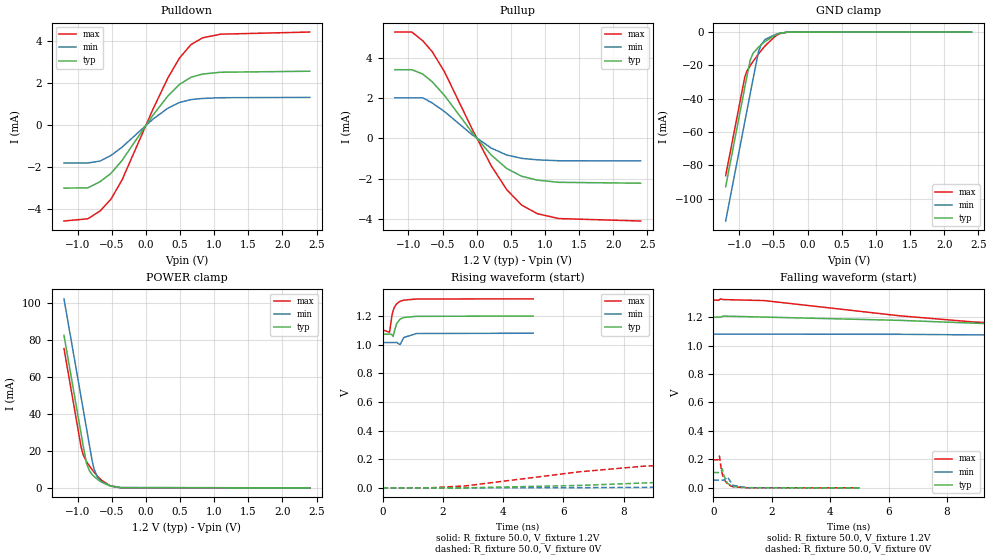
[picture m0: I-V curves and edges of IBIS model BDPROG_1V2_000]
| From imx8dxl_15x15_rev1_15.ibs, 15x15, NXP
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[Model] BDPROG_1V2_000
Model_type I/O
Polarity   Non-Inverting
Enable   Active-Low
| CAP_THRESHOLD on pad IO is "CMOS" :
| Rising=10.0% of vdde1v2   Falling=90.0% of vdde1v2
| C_comp min and max val. don't necessarily correlate with the min and max pvt
| but are the smallest and greatest pad capacitance found.
| var   typ   min   max
C_comp   2.03145pF  2.00990pF  2.05295pF
Vinl = 324.0mV
Vinh = 924.0mV
Vmeas = 600.0mV   | Reference voltage for timing measurements
Cref  = 15.0pF   | Timing specification test load capacitance value
Rref  = 1.0MOhm   | Timing specification test load resistance value
Vref  = 1.2V   | Timing specification test load voltage
[Model Spec]
| TIME_THRESHOLD on pin ZI is "CORE" :
| Rising=50.0% of vdd   Falling=50.0% of vdd
Vinl 420.00000mV 378.00000mV 462.00000mV
Vinh 780.00000mV 702.00000mV 858.00000mV
| variable   typ   min   max
[Temperature Range] 25.0 125.0 -40.0
| variable   typ   min   max
[Voltage Range] 1.2V 1.08V 1.32V
| variable   typ   min   max
[POWER Clamp Reference] 1.2V 1.08V 1.32V
| variable   typ   min   max
[GND Clamp Reference] 0V 0V 0V
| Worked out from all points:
|   slope of the pulldown table from 0 to 0.18 V, typ, clamps not added: 221 ohm
|   slope of the pullup table from 0 to 0.18 V, typ, clamps not added: 253 ohm
|   GND clamp passes 1 mA (typ) near -0.42 V on its own axis
|   POWER clamp passes 1 mA (typ) near -0.53 V on its own axis
|   rising waveform, R_fixture 50.0, V_fixture 1.2V: 20-80 % time 162ps typ, 162ps min, 164ps max; typ from 1.07 V to 1.2 V
|   falling waveform, R_fixture 50.0, V_fixture 1.2V: 20-80 % time 12ns typ, 22.9ns min, 6.95ns max; typ from 1.2 V to 1.07 V
|   rising waveform, R_fixture 50.0, V_fixture 0V: 20-80 % time 9.6ns typ, 18.1ns min, 5.33ns max; typ from 0 V to 0.108 V
|   falling waveform, R_fixture 50.0, V_fixture 0V: 20-80 % time 175ps typ, 172ps min, 171ps max; typ from 0.108 V to 0 V
[POWER Clamp]
-1.2V     82.47mA    102.2mA    75.29mA
-950mV    29.35mA    49.08mA    22.16mA
-920mV    22.97mA    42.71mA    17.94mA
-870mV    13.26mA    32.08mA    14.19mA
-830mV    9.388mA    23.58mA    11.94mA
-790mV    7.28mA     15.08mA    9.891mA
-760mV    6.153mA    10.18mA    8.467mA
-710mV    4.618mA    5.741mA    6.312mA
-650mV    3.105mA    3.261mA    4.124mA
-520mV    918uA      1.114mA    1.041mA
-370mV    66.09uA    190.5uA    36.14uA
2.4V      0A         0A         0A
[GND Clamp]
-1.2V     -92.79mA   -113.4mA   -86.23mA
-920mV    -33.29mA   -53.93mA   -27.01mA
-890mV    -26.92mA   -47.56mA   -23.57mA
-840mV    -16.83mA   -36.93mA   -20.11mA
-800mV    -12.88mA   -28.43mA   -17.73mA
-720mV    -9.099mA   -11.98mA   -13.24mA
-680mV    -7.622mA   -7.471mA   -11.12mA
-620mV    -5.599mA   -4.428mA   -8.161mA
-470mV    -1.717mA   -1.41mA    -2.413mA
-410mV    -792.7uA   -748.8uA   -1.042mA
-300mV    -72.27uA   -128.2uA   -61.83uA
2.4V      12.46nA    838.5nA    861.8pA
| variable   typ   min   max
[Pullup Reference] 1.2V 1.08V 1.32V
| variable   typ   min   max
[Pulldown Reference] 0V 0V 0V
[Pullup]
-1.2V     3.414mA    2.016mA    5.286mA
-950mV    3.414mA    2.016mA    5.286mA
-790mV    3.196mA    2.016mA    4.849mA
-650mV    2.805mA    1.756mA    4.299mA
-470mV    2.125mA    1.328mA    3.292mA
-70mV     301.4uA    184.3uA    480.9uA
210mV     -819.3uA   -477.7uA   -1.349mA
440mV     -1.499mA   -827.6uA   -2.553mA
660mV     -1.885mA   -993.6uA   -3.322mA
890mV     -2.076mA   -1.067mA   -3.745mA
1.2V      -2.183mA   -1.111mA   -3.984mA
2.4V      -2.227mA   -1.119mA   -4.106mA
[Pulldown]
-1.2V     -2.999mA   -1.803mA   -4.567mA
-850mV    -2.986mA   -1.803mA   -4.461mA
-670mV    -2.691mA   -1.711mA   -4.084mA
-510mV    -2.289mA   -1.439mA   -3.516mA
-350mV    -1.683mA   -1.051mA   -2.612mA
100mV     461.5uA    278.5uA    735.6uA
320mV     1.382mA    804uA      2.238mA
490mV     1.937mA    1.08mA     3.191mA
660mV     2.281mA    1.218mA    3.838mA
830mV     2.436mA    1.272mA    4.161mA
1.1V      2.521mA    1.307mA    4.335mA
2.4V      2.569mA    1.322mA    4.436mA
[Ramp]
dV/dt_r 64.67689mV/9.5982ns 32.22194mV/18.06622ns 118.34546mV/5.32652ns
dV/dt_f 75.44366mV/12.0013ns 37.52591mV/21.44012ns 130.11031mV/6.95246ns
R_load = 50.0
| Removed startup time: 0s 0s 0s  .
| Removed end time: 5.0ns.
[Rising Waveform]
R_fixture   = 50.0
V_fixture   = 1.2V
V_fixture_min = 1.08V
V_fixture_max = 1.32V
0s        1.074V     1.015V     1.103V
234ps     1.074V     1.015V     1.087V
308ps     1.071V     1.015V     1.198V
351ps     1.057V     1.015V     1.237V
386ps     1.088V     1.015V     1.258V
466ps     1.146V     1.016V     1.285V
581ps     1.178V     999.8mV    1.303V
707ps     1.19V      1.05V      1.311V
1.122ns   1.198V     1.078V     1.319V
5ns       1.2V       1.08V      1.32V
| Removed startup time: 0s 0s 0s  .
| Removed end time: 60.0ns.
[Falling Waveform]
R_fixture   = 50.0
V_fixture   = 1.2V
V_fixture_min = 1.08V
V_fixture_max = 1.32V
0s        1.2V       1.08V      1.32V
180ps     1.2V       1.08V      1.318V
240ps     1.199V     1.08V      1.328V
340ps     1.207V     1.08V      1.323V
1.74ns    1.2V       1.08V      1.316V
6.38ns    1.177V     1.079V     1.209V
8.94ns    1.157V     1.075V     1.165V
15.04ns   1.115V     1.064V     1.119V
28.8ns    1.081V     1.037V     1.104V
60ns      1.074V     1.015V     1.103V
| Removed startup time: 0s 0s 0s  .
| Removed end time: 60.0ns.
[Rising Waveform]
R_fixture   = 50.0
V_fixture   = 0V
V_fixture_min = 0V
V_fixture_max = 0V
0s        28.6nV     1.462uV    18.95nV
1.62ns    -93.21uV   -51.64uV   617.1uV
2.76ns    182.6uV    -35.71uV   13.7mV
6.54ns    16.71mV    1.217mV    112mV
8.64ns    33.54mV    3.383mV    150.6mV
10.78ns   51.38mV    6.514mV    172.8mV
13.52ns   70.58mV    11.56mV    186.2mV
18.36ns   91.38mV    21.93mV    194.7mV
25.48ns   102.9mV    35.55mV    196.9mV
60ns      107.8mV    53.7mV     197.2mV
| Removed startup time: 0s 0s 0s  .
| Removed end time: 4.999ns.
[Falling Waveform]
R_fixture   = 50.0
V_fixture   = 0V
V_fixture_min = 0V
V_fixture_max = 0V
0s        107.8mV    54.54mV    197.2mV
161ps     107.8mV    54.54mV    196.7mV
208ps     107.7mV    54.53mV    223.7mV
265ps     117.5mV    54.57mV    137.3mV
304ps     133.8mV    54.6mV     97.44mV
367ps     81.44mV    53.79mV    58.53mV
486ps     30.71mV    75.45mV    24.78mV
671ps     9.168mV    17.53mV    7.149mV
1.157ns   749uV      1.208mV    534.8uV
4.999ns   25.73uV    20.62uV    28.93uV
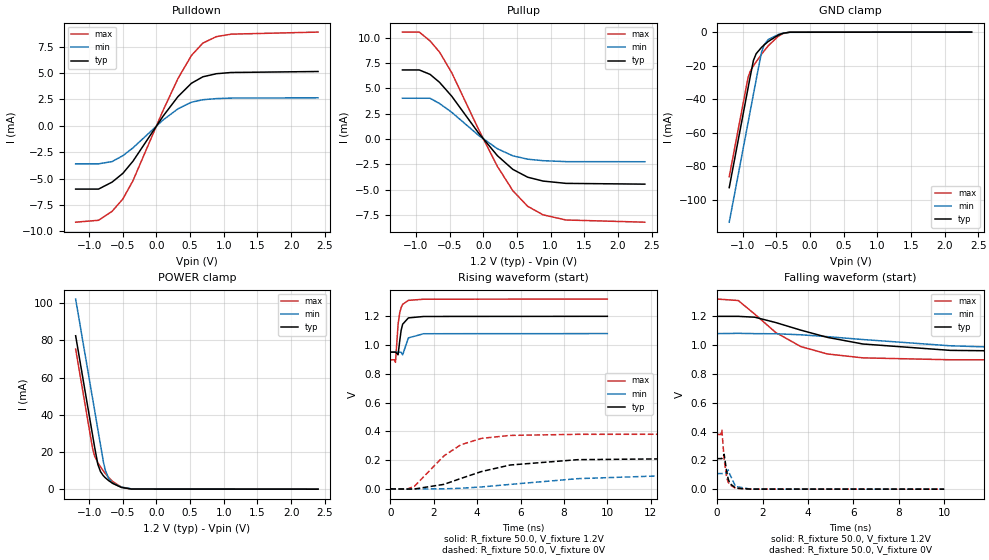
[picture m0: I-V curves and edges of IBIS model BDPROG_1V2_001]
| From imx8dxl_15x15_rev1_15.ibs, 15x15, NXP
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[Model] BDPROG_1V2_001
Model_type I/O
Polarity   Non-Inverting
Enable   Active-Low
| CAP_THRESHOLD on pad IO is "CMOS" :
| Rising=10.0% of vdde1v2   Falling=90.0% of vdde1v2
| C_comp min and max val. don't necessarily correlate with the min and max pvt
| but are the smallest and greatest pad capacitance found.
| var   typ   min   max
C_comp   2.03110pF  2.00945pF  2.05275pF
Vinl = 324.0mV
Vinh = 924.0mV
Vmeas = 600.0mV   | Reference voltage for timing measurements
Cref  = 15.0pF   | Timing specification test load capacitance value
Rref  = 1.0MOhm   | Timing specification test load resistance value
Vref  = 1.2V   | Timing specification test load voltage
[Model Spec]
| TIME_THRESHOLD on pin ZI is "CORE" :
| Rising=50.0% of vdd   Falling=50.0% of vdd
Vinl 420.00000mV 378.00000mV 462.00000mV
Vinh 780.00000mV 702.00000mV 858.00000mV
| variable   typ   min   max
[Temperature Range] 25.0 125.0 -40.0
| variable   typ   min   max
[Voltage Range] 1.2V 1.08V 1.32V
| variable   typ   min   max
[POWER Clamp Reference] 1.2V 1.08V 1.32V
| variable   typ   min   max
[GND Clamp Reference] 0V 0V 0V
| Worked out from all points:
|   slope of the pulldown table from 0 to 0.18 V, typ, clamps not added: 111 ohm
|   slope of the pullup table from 0 to 0.18 V, typ, clamps not added: 127 ohm
|   GND clamp passes 1 mA (typ) near -0.43 V on its own axis
|   POWER clamp passes 1 mA (typ) near -0.53 V on its own axis
|   rising waveform, R_fixture 50.0, V_fixture 1.2V: 20-80 % time 168ps typ, 182ps min, 165ps max; typ from 0.951 V to 1.2 V
|   falling waveform, R_fixture 50.0, V_fixture 1.2V: 20-80 % time 4ns typ, 7.65ns min, 2.31ns max; typ from 1.2 V to 0.951 V
|   rising waveform, R_fixture 50.0, V_fixture 0V: 20-80 % time 2.98ns typ, 5.7ns min, 1.67ns max; typ from 0 V to 0.212 V
|   falling waveform, R_fixture 50.0, V_fixture 0V: 20-80 % time 174ps typ, 206ps min, 165ps max; typ from 0.212 V to 0 V
[POWER Clamp]
-1.2V     82.47mA    102.2mA    75.29mA
-950mV    29.35mA    49.08mA    22.16mA
-920mV    22.97mA    42.71mA    17.94mA
-870mV    13.26mA    32.08mA    14.19mA
-830mV    9.388mA    23.58mA    11.94mA
-790mV    7.28mA     15.08mA    9.891mA
-760mV    6.153mA    10.18mA    8.467mA
-710mV    4.618mA    5.741mA    6.312mA
-650mV    3.105mA    3.261mA    4.124mA
-520mV    918uA      1.114mA    1.041mA
-370mV    66.09uA    190.5uA    36.14uA
2.4V      0A         0A         0A
[GND Clamp]
-1.2V     -92.79mA   -113.4mA   -86.23mA
-920mV    -33.29mA   -53.93mA   -27.01mA
-890mV    -26.92mA   -47.56mA   -23.57mA
-840mV    -16.83mA   -36.93mA   -20.11mA
-800mV    -12.88mA   -28.43mA   -17.73mA
-720mV    -9.099mA   -11.98mA   -13.24mA
-680mV    -7.622mA   -7.471mA   -11.12mA
-620mV    -5.599mA   -4.428mA   -8.161mA
-470mV    -1.717mA   -1.41mA    -2.413mA
-400mV    -678.8uA   -662.4uA   -876.2uA
-300mV    -72.27uA   -128.2uA   -61.83uA
2.4V      12.46nA    838.5nA    861.8pA
| variable   typ   min   max
[Pullup Reference] 1.2V 1.08V 1.32V
| variable   typ   min   max
[Pulldown Reference] 0V 0V 0V
[Pullup]
-1.2V     6.828mA    4.033mA    10.57mA
-950mV    6.828mA    4.033mA    10.57mA
-790mV    6.393mA    4.033mA    9.698mA
-650mV    5.609mA    3.514mA    8.599mA
-470mV    4.251mA    2.657mA    6.584mA
-70mV     602.8uA    368.8uA    962uA
210mV     -1.639mA   -956.2uA   -2.698mA
440mV     -2.998mA   -1.657mA   -5.106mA
660mV     -3.77mA    -1.99mA    -6.645mA
890mV     -4.153mA   -2.138mA   -7.491mA
1.23V     -4.38mA    -2.23mA    -7.998mA
2.4V      -4.456mA   -2.241mA   -8.215mA
[Pulldown]
-1.2V     -5.997mA   -3.607mA   -9.133mA
-860mV    -5.997mA   -3.607mA   -8.951mA
-660mV    -5.342mA   -3.395mA   -8.112mA
-500mV    -4.516mA   -2.838mA   -6.942mA
-350mV    -3.366mA   -2.103mA   -5.224mA
100mV     923.1uA    557.3uA    1.471mA
320mV     2.764mA    1.609mA    4.477mA
520mV     4.028mA    2.229mA    6.66mA
690mV     4.639mA    2.467mA    7.832mA
890mV     4.929mA    2.571mA    8.443mA
1.11V     5.045mA    2.621mA    8.677mA
2.4V      5.139mA    2.648mA    8.872mA
[Ramp]
dV/dt_r 127.30357mV/2.97994ns 65.04281mV/5.69568ns 228.15538mV/1.66687ns
dV/dt_f 149.19334mV/4.00144ns 77.64787mV/7.65239ns 253.69517mV/2.30909ns
R_load = 50.0
| Removed startup time: 0s 0s 0s  .
| Removed end time: 10.0ns.
[Rising Waveform]
R_fixture   = 50.0
V_fixture   = 1.2V
V_fixture_min = 1.08V
V_fixture_max = 1.32V
0s        951.3mV    950.6mV    897.2mV
194ps     951.3mV    950.6mV    897.9mV
238ps     951.3mV    950.6mV    880.1mV
358ps     932.5mV    950.6mV    1.145V
434ps     1.029V     950.7mV    1.225V
498ps     1.102V     949.8mV    1.261V
568ps     1.145V     932.4mV    1.283V
832ps     1.189V     1.05V      1.311V
1.536ns   1.199V     1.079V     1.319V
10ns      1.2V       1.08V      1.32V
| Removed startup time: 0s 0s 0s  .
| Removed end time: 50.0ns.
[Falling Waveform]
R_fixture   = 50.0
V_fixture   = 1.2V
V_fixture_min = 1.08V
V_fixture_max = 1.32V
0s        1.2V       1.08V      1.32V
930ps     1.2V       1.082V     1.31V
1.66ns    1.194V     1.08V      1.215V
2.58ns    1.157V     1.079V     1.088V
3.69ns    1.104V     1.072V     989.9mV
4.86ns    1.054V     1.059V     938.7mV
6.42ns    1.008V     1.039V     911.7mV
10.27ns   963.7mV    995.5mV    898.5mV
17.17ns   952.2mV    961.2mV    897.2mV
50ns      951.3mV    950.6mV    897.2mV
| Removed startup time: 0s 0s 0s  .
| Removed end time: 50.0ns.
[Rising Waveform]
R_fixture   = 50.0
V_fixture   = 0V
V_fixture_min = 0V
V_fixture_max = 0V
0s        23.45nV    1.263uV    14.77nV
780ps     -805.7uV   -1.627mV   -317.3uV
1.1ns     -522.4uV   -454.3uV   16.86mV
2.47ns    31.75mV    737.5uV    229.6mV
3.24ns    72.27mV    4.677mV    306.8mV
4.2ns     120.9mV    13.76mV    351.4mV
5.52ns    166.3mV    31.44mV    372.1mV
8.64ns    203.5mV    71.49mV    379.7mV
14.61ns   211.8mV    101.7mV    380.3mV
50ns      212.2mV    108.4mV    380.3mV
| Removed startup time: 0s 0s 0s  .
| Removed end time: 10.0ns.
[Falling Waveform]
R_fixture   = 50.0
V_fixture   = 0V
V_fixture_min = 0V
V_fixture_max = 0V
0s        212.2mV    108.4mV    380.3mV
162ps     212.2mV    108.4mV    379.7mV
210ps     212mV      108.4mV    409.7mV
310ps     242.1mV    108.5mV    208.1mV
418ps     124.7mV    115.8mV    83.06mV
488ps     70.9mV     133.9mV    48.91mV
560ps     39.73mV    101.9mV    29.64mV
818ps     7.306mV    18.36mV    5.66mV
1.468ns   479.1uV    644.1uV    262.1uV
10ns      7.665uV    25.72uV    1.235uV
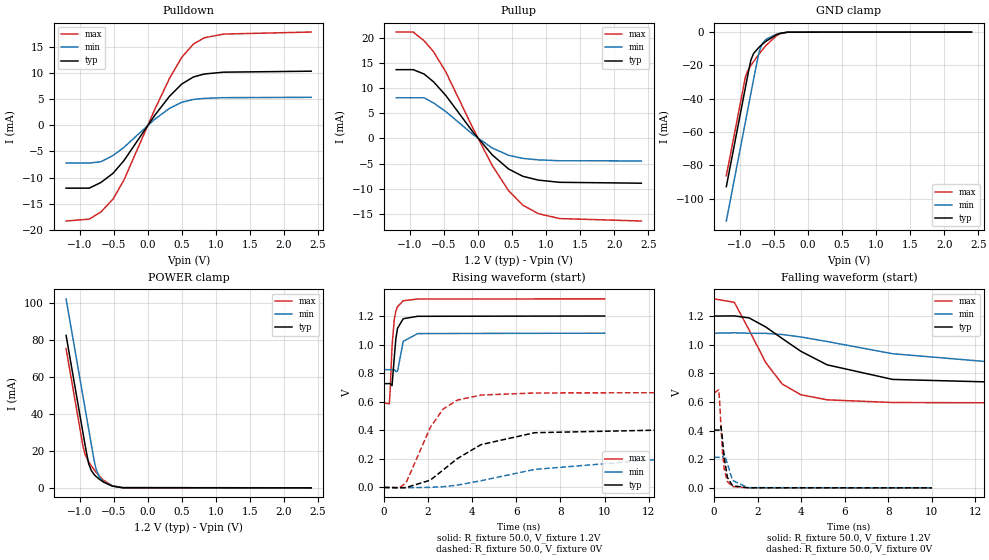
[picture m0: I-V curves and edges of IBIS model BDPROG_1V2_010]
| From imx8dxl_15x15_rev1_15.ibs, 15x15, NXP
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[Model] BDPROG_1V2_010
Model_type I/O
Polarity   Non-Inverting
Enable   Active-Low
| CAP_THRESHOLD on pad IO is "CMOS" :
| Rising=10.0% of vdde1v2   Falling=90.0% of vdde1v2
| C_comp min and max val. don't necessarily correlate with the min and max pvt
| but are the smallest and greatest pad capacitance found.
| var   typ   min   max
C_comp   2.03030pF  2.00855pF  2.05215pF
Vinl = 324.0mV
Vinh = 924.0mV
Vmeas = 600.0mV   | Reference voltage for timing measurements
Cref  = 15.0pF   | Timing specification test load capacitance value
Rref  = 1.0MOhm   | Timing specification test load resistance value
Vref  = 1.2V   | Timing specification test load voltage
[Model Spec]
| TIME_THRESHOLD on pin ZI is "CORE" :
| Rising=50.0% of vdd   Falling=50.0% of vdd
Vinl 420.00000mV 378.00000mV 462.00000mV
Vinh 780.00000mV 702.00000mV 858.00000mV
| variable   typ   min   max
[Temperature Range] 25.0 125.0 -40.0
| variable   typ   min   max
[Voltage Range] 1.2V 1.08V 1.32V
| variable   typ   min   max
[POWER Clamp Reference] 1.2V 1.08V 1.32V
| variable   typ   min   max
[GND Clamp Reference] 0V 0V 0V
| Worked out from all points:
|   slope of the pulldown table from 0 to 0.18 V, typ, clamps not added: 55.2 ohm
|   slope of the pullup table from 0 to 0.18 V, typ, clamps not added: 63.3 ohm
|   GND clamp passes 1 mA (typ) near -0.43 V on its own axis
|   POWER clamp passes 1 mA (typ) near -0.53 V on its own axis
|   rising waveform, R_fixture 50.0, V_fixture 1.2V: 20-80 % time 174ps typ, 200ps min, 167ps max; typ from 0.727 V to 1.2 V
|   falling waveform, R_fixture 50.0, V_fixture 1.2V: 20-80 % time 3.34ns typ, 6.64ns min, 1.66ns max; typ from 1.2 V to 0.727 V
|   rising waveform, R_fixture 50.0, V_fixture 0V: 20-80 % time 2.42ns typ, 4.69ns min, 1.23ns max; typ from 0 V to 0.403 V
|   falling waveform, R_fixture 50.0, V_fixture 0V: 20-80 % time 204ps typ, 267ps min, 183ps max; typ from 0.403 V to 0 V
[POWER Clamp]
-1.2V     82.47mA    102.2mA    75.29mA
-950mV    29.35mA    49.08mA    22.16mA
-920mV    22.97mA    42.71mA    17.94mA
-870mV    13.26mA    32.08mA    14.19mA
-830mV    9.388mA    23.58mA    11.94mA
-790mV    7.28mA     15.08mA    9.891mA
-760mV    6.153mA    10.18mA    8.467mA
-710mV    4.618mA    5.741mA    6.312mA
-650mV    3.105mA    3.261mA    4.124mA
-520mV    918uA      1.114mA    1.041mA
-370mV    66.09uA    190.5uA    36.14uA
2.4V      0A         0A         0A
[GND Clamp]
-1.2V     -92.79mA   -113.4mA   -86.23mA
-920mV    -33.29mA   -53.93mA   -27.01mA
-890mV    -26.92mA   -47.56mA   -23.57mA
-840mV    -16.83mA   -36.93mA   -20.11mA
-800mV    -12.88mA   -28.43mA   -17.73mA
-720mV    -9.099mA   -11.98mA   -13.24mA
-680mV    -7.622mA   -7.471mA   -11.12mA
-620mV    -5.599mA   -4.428mA   -8.161mA
-470mV    -1.717mA   -1.41mA    -2.413mA
-410mV    -792.7uA   -748.8uA   -1.042mA
-300mV    -72.27uA   -128.2uA   -61.83uA
2.4V      12.46nA    838.5nA    861.8pA
| variable   typ   min   max
[Pullup Reference] 1.2V 1.08V 1.32V
| variable   typ   min   max
[Pulldown Reference] 0V 0V 0V
[Pullup]
-1.2V     13.66mA    8.065mA    21.14mA
-950mV    13.66mA    8.065mA    21.14mA
-790mV    12.79mA    8.065mA    19.4mA
-650mV    11.22mA    7.028mA    17.2mA
-470mV    8.502mA    5.315mA    13.17mA
-70mV     1.206mA    737.6uA    1.924mA
210mV     -3.278mA   -1.913mA   -5.396mA
450mV     -6.089mA   -3.358mA   -10.39mA
660mV     -7.542mA   -3.98mA    -13.29mA
890mV     -8.306mA   -4.277mA   -14.98mA
1.2V      -8.736mA   -4.45mA    -15.94mA
2.4V      -8.914mA   -4.483mA   -16.43mA
[Pulldown]
-1.2V     -12.01mA   -7.227mA   -18.28mA
-860mV    -12.01mA   -7.227mA   -17.92mA
-690mV    -10.94mA   -6.971mA   -16.57mA
-510mV    -9.17mA    -5.771mA   -14.08mA
-350mV    -6.746mA   -4.217mA   -10.46mA
100mV     1.85mA     1.118mA    2.948mA
320mV     5.542mA    3.229mA    8.971mA
500mV     7.874mA    4.387mA    12.98mA
670mV     9.203mA    4.916mA    15.49mA
830mV     9.77mA     5.118mA    16.68mA
1.11V     10.12mA    5.261mA    17.39mA
2.4V      10.31mA    5.317mA    17.78mA
[Ramp]
dV/dt_r 242.09871mV/2.42005ns 127.7254mV/4.69138ns 397.84126mV/1.23243ns
dV/dt_f 283.93319mV/3.33551ns 153.41934mV/6.6439ns 436.07219mV/1.65617ns
R_load = 50.0
| Removed startup time: 0s 0s 0s  .
| Removed end time: 10.0ns.
[Rising Waveform]
R_fixture   = 50.0
V_fixture   = 1.2V
V_fixture_min = 1.08V
V_fixture_max = 1.32V
0s        726.8mV    824.3mV    593.2mV
242ps     726.7mV    824.3mV    584.3mV
282ps     727.5mV    824.3mV    674.7mV
366ps     712.5mV    824.3mV    985.8mV
468ps     909.3mV    825.2mV    1.177V
540ps     1.041V     812mV      1.234V
616ps     1.114V     812.8mV    1.266V
874ps     1.181V     1.023V     1.307V
1.528ns   1.198V     1.077V     1.319V
10ns      1.2V       1.08V      1.32V
| Removed startup time: 0s 0s 0s  .
| Removed end time: 50.0ns.
[Falling Waveform]
R_fixture   = 50.0
V_fixture   = 1.2V
V_fixture_min = 1.08V
V_fixture_max = 1.32V
0s        1.2V       1.08V      1.32V
930ps     1.201V     1.083V     1.296V
1.61ns    1.187V     1.08V      1.102V
2.37ns    1.124V     1.079V     875.2mV
3.13ns    1.043V     1.071V     725.2mV
3.98ns    954.3mV    1.054V     650.6mV
5.19ns    859.3mV    1.022V     614.8mV
8.2ns     757.3mV    936.8mV    596mV
15.48ns   728.3mV    844.1mV    593.1mV
50ns      726.8mV    824.3mV    593.2mV
| Removed startup time: 0s 0s 0s  .
| Removed end time: 50.0ns.
[Rising Waveform]
R_fixture   = 50.0
V_fixture   = 0V
V_fixture_min = 0V
V_fixture_max = 0V
0s        16.87nV    971.4nV    10.17nV
710ps     -2.17mV    -2.802mV   -1.024mV
1ns       -1.119mV   -1.756mV   31.17mV
2.1ns     51.02mV    583uV      420mV
2.68ns    122mV      5.245mV    548.5mV
3.33ns    202.4mV    16.13mV    611.4mV
4.4ns     299.7mV    46.95mV    646.6mV
6.83ns    383.2mV    126.3mV    661.3mV
12.91ns   402.7mV    202.2mV    663.2mV
50ns      403.5mV    212.9mV    663.1mV
| Removed startup time: 0s 0s 0s  .
| Removed end time: 10.0ns.
[Falling Waveform]
R_fixture   = 50.0
V_fixture   = 0V
V_fixture_min = 0V
V_fixture_max = 0V
0s        403.5mV    212.9mV    663.1mV
214ps     403.2mV    212.9mV    684.4mV
254ps     406.8mV    212.9mV    609.5mV
320ps     428.3mV    212.9mV    418.4mV
392ps     327.9mV    213.7mV    241.4mV
464ps     213.9mV    237.7mV    134.1mV
612ps     73.37mV    170.3mV    43.97mV
846ps     14.59mV    51.75mV    9.08mV
1.548ns   741.9uV    1.346mV    349uV
10ns      9.146uV    38.84uV    1.077uV
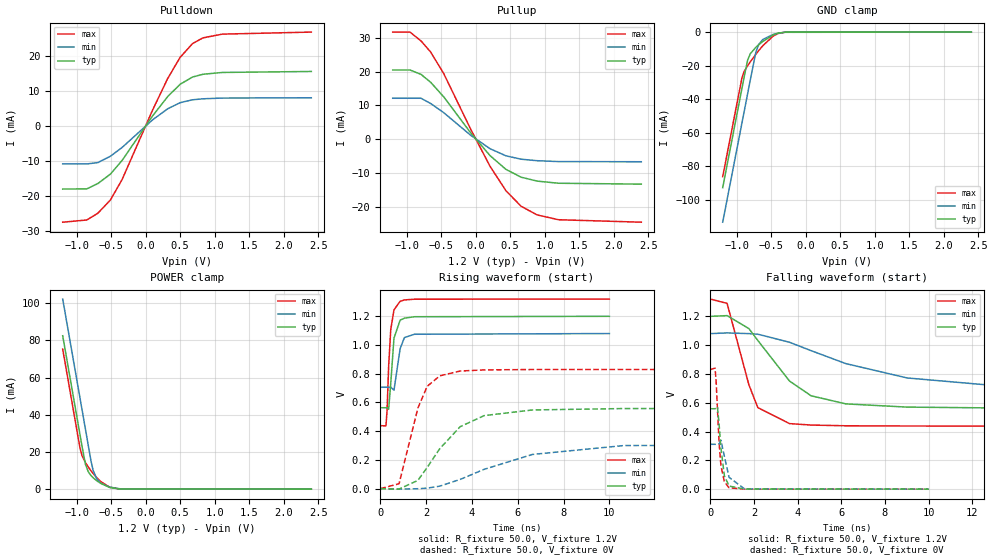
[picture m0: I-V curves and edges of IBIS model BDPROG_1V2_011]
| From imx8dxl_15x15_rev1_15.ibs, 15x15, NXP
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[Model] BDPROG_1V2_011
Model_type I/O
Polarity   Non-Inverting
Enable   Active-Low
| CAP_THRESHOLD on pad IO is "CMOS" :
| Rising=10.0% of vdde1v2   Falling=90.0% of vdde1v2
| C_comp min and max val. don't necessarily correlate with the min and max pvt
| but are the smallest and greatest pad capacitance found.
| var   typ   min   max
C_comp   2.02935pF  2.00750pF  2.05140pF
Vinl = 324.0mV
Vinh = 924.0mV
Vmeas = 600.0mV   | Reference voltage for timing measurements
Cref  = 15.0pF   | Timing specification test load capacitance value
Rref  = 1.0MOhm   | Timing specification test load resistance value
Vref  = 1.2V   | Timing specification test load voltage
[Model Spec]
| TIME_THRESHOLD on pin ZI is "CORE" :
| Rising=50.0% of vdd   Falling=50.0% of vdd
Vinl 420.00000mV 378.00000mV 462.00000mV
Vinh 780.00000mV 702.00000mV 858.00000mV
| variable   typ   min   max
[Temperature Range] 25.0 125.0 -40.0
| variable   typ   min   max
[Voltage Range] 1.2V 1.08V 1.32V
| variable   typ   min   max
[POWER Clamp Reference] 1.2V 1.08V 1.32V
| variable   typ   min   max
[GND Clamp Reference] 0V 0V 0V
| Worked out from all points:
|   slope of the pulldown table from 0 to 0.18 V, typ, clamps not added: 36.8 ohm
|   slope of the pullup table from 0 to 0.18 V, typ, clamps not added: 42.2 ohm
|   GND clamp passes 1 mA (typ) near -0.43 V on its own axis
|   POWER clamp passes 1 mA (typ) near -0.53 V on its own axis
|   rising waveform, R_fixture 50.0, V_fixture 1.2V: 20-80 % time 178ps typ, 211ps min, 167ps max; typ from 0.564 V to 1.2 V
|   falling waveform, R_fixture 50.0, V_fixture 1.2V: 20-80 % time 2.13ns typ, 4.77ns min, 953ps max; typ from 1.2 V to 0.564 V
|   rising waveform, R_fixture 50.0, V_fixture 0V: 20-80 % time 1.73ns typ, 3.53ns min, 803ps max; typ from 0 V to 0.559 V
|   falling waveform, R_fixture 50.0, V_fixture 0V: 20-80 % time 216ps typ, 290ps min, 190ps max; typ from 0.559 V to 0 V
[POWER Clamp]
-1.2V     82.47mA    102.2mA    75.29mA
-950mV    29.35mA    49.08mA    22.16mA
-920mV    22.97mA    42.71mA    17.94mA
-870mV    13.26mA    32.08mA    14.19mA
-830mV    9.388mA    23.58mA    11.94mA
-790mV    7.28mA     15.08mA    9.891mA
-760mV    6.153mA    10.18mA    8.467mA
-710mV    4.618mA    5.741mA    6.312mA
-650mV    3.105mA    3.261mA    4.124mA
-520mV    918uA      1.114mA    1.041mA
-370mV    66.09uA    190.5uA    36.14uA
2.4V      0A         0A         0A
[GND Clamp]
-1.2V     -92.79mA   -113.4mA   -86.23mA
-920mV    -33.29mA   -53.93mA   -27.01mA
-890mV    -26.92mA   -47.56mA   -23.57mA
-840mV    -16.83mA   -36.93mA   -20.11mA
-800mV    -12.88mA   -28.43mA   -17.73mA
-720mV    -9.099mA   -11.98mA   -13.24mA
-680mV    -7.622mA   -7.471mA   -11.12mA
-620mV    -5.599mA   -4.428mA   -8.161mA
-470mV    -1.717mA   -1.41mA    -2.413mA
-400mV    -678.8uA   -662.4uA   -876.2uA
-300mV    -72.27uA   -128.2uA   -61.83uA
2.4V      12.46nA    838.5nA    861.8pA
| variable   typ   min   max
[Pullup Reference] 1.2V 1.08V 1.32V
| variable   typ   min   max
[Pulldown Reference] 0V 0V 0V
[Pullup]
-1.2V     20.48mA    12.1mA     31.72mA
-950mV    20.48mA    12.1mA     31.72mA
-790mV    19.18mA    12.1mA     29.1mA
-650mV    16.83mA    10.54mA    25.8mA
-460mV    12.49mA    7.812mA    19.36mA
-70mV     1.809mA    1.107mA    2.886mA
210mV     -4.917mA   -2.869mA   -8.095mA
440mV     -8.995mA   -4.972mA   -15.32mA
660mV     -11.31mA   -5.971mA   -19.94mA
890mV     -12.46mA   -6.416mA   -22.48mA
1.2V      -13.1mA    -6.676mA   -23.92mA
2.4V      -13.37mA   -6.726mA   -24.65mA
[Pulldown]
-1.2V     -18mA      -10.85mA   -27.43mA
-850mV    -17.94mA   -10.85mA   -26.8mA
-690mV    -16.42mA   -10.46mA   -24.86mA
-510mV    -13.76mA   -8.662mA   -21.13mA
-340mV    -9.853mA   -6.161mA   -15.29mA
100mV     2.778mA    1.679mA    4.425mA
320mV     8.319mA    4.85mA     13.46mA
500mV     11.82mA    6.589mA    19.48mA
680mV     13.89mA    7.412mA    23.41mA
830mV     14.67mA    7.687mA    25.03mA
1.11V     15.19mA    7.903mA    26.1mA
2.4V      15.47mA    7.987mA    26.68mA
[Ramp]
dV/dt_r 335.22078mV/1.72861ns 186.86484mV/3.52921ns 497.80181mV/802.5469ps
dV/dt_f 381.87667mV/2.12803ns 224.36176mV/4.76836ns 528.90856mV/952.86422ps
R_load = 50.0
| Removed startup time: 0s 0s 0s  .
| Removed end time: 10.0ns.
[Rising Waveform]
R_fixture   = 50.0
V_fixture   = 1.2V
V_fixture_min = 1.08V
V_fixture_max = 1.32V
0s        563.5mV    706.1mV    438.5mV
248ps     563.5mV    706.1mV    437.4mV
296ps     564mV      706.1mV    543.9mV
366ps     553.3mV    706mV      854.2mV
458ps     735.2mV    706.7mV    1.109V
598ps     1.048V     685.5mV    1.245V
866ps     1.173V     974.3mV    1.304V
1.054ns   1.187V     1.052V     1.314V
1.492ns   1.197V     1.075V     1.319V
10ns      1.2V       1.08V      1.32V
| Removed startup time: 0s 0s 0s  .
| Removed end time: 50.0ns.
[Falling Waveform]
R_fixture   = 50.0
V_fixture   = 1.2V
V_fixture_min = 1.08V
V_fixture_max = 1.32V
0s        1.2V       1.08V      1.32V
770ps     1.205V     1.085V     1.29V
1.77ns    1.115V     1.08V      723.9mV
2.18ns    1.032V     1.076V     566.3mV
3.63ns    750.8mV    1.02V      455.3mV
4.62ns    648.4mV    961.7mV    445.1mV
6.21ns    592.1mV    871.8mV    440.1mV
9.02ns    569.8mV    772.2mV    438.5mV
12.6ns    564.6mV    725mV      438.4mV
50ns      563.5mV    706.1mV    438.5mV
| Removed startup time: 0s 0s 0s  .
| Removed end time: 50.0ns.
[Rising Waveform]
R_fixture   = 50.0
V_fixture   = 0V
V_fixture_min = 0V
V_fixture_max = 0V
0s        12.87nV    770.4nV    7.686nV
820ps     -2.721mV   -3.423mV   34.56mV
1.64ns    57.41mV    -303.8uV   560.7mV
2.05ns    148.5mV    3.732mV    713.2mV
2.6ns     279.2mV    17.7mV     785.9mV
3.49ns    431.7mV    64.53mV    819.1mV
4.53ns    508.5mV    134.6mV    826.9mV
6.64ns    548mV      238.3mV    829.5mV
10.64ns   557.9mV    300.3mV    829.8mV
50ns      558.7mV    311.4mV    829.7mV
| Removed startup time: 0s 0s 0s  .
| Removed end time: 10.0ns.
[Falling Waveform]
R_fixture   = 50.0
V_fixture   = 0V
V_fixture_min = 0V
V_fixture_max = 0V
0s        558.7mV    311.4mV    829.7mV
220ps     558.3mV    311.4mV    840.5mV
268ps     567.3mV    311.5mV    749.4mV
330ps     570.6mV    311.3mV    551.4mV
408ps     442mV      315.6mV    312.4mV
488ps     284.3mV    339.9mV    164.8mV
646ps     93.02mV    227.9mV    51.16mV
862ps     21.66mV    82.02mV    9.233mV
1.566ns   986.6uV    2.316mV    372uV
10ns      4.474uV    32.48uV    356.2nV
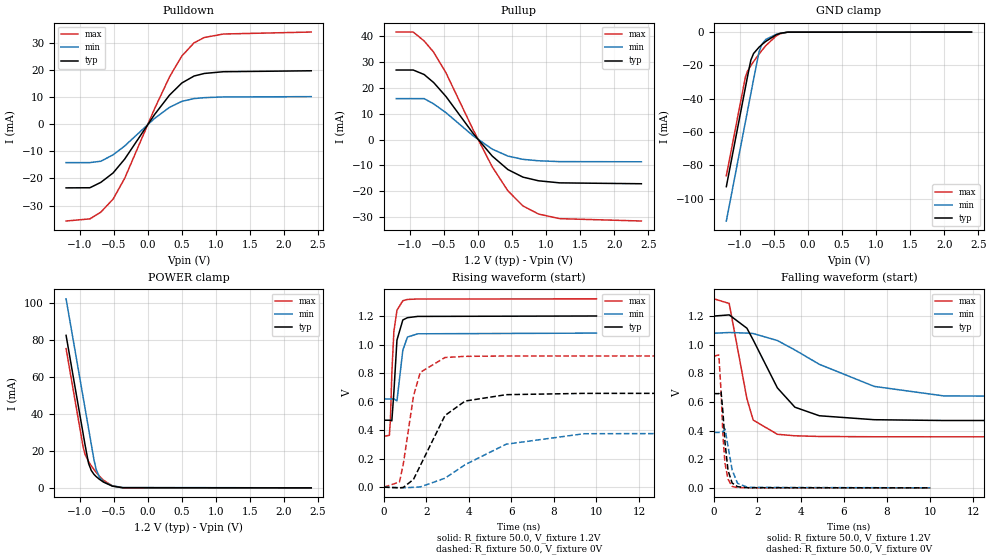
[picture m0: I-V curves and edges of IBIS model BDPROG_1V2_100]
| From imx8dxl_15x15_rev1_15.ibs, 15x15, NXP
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[Model] BDPROG_1V2_100
Model_type I/O
Polarity   Non-Inverting
Enable   Active-Low
| CAP_THRESHOLD on pad IO is "CMOS" :
| Rising=10.0% of vdde1v2   Falling=90.0% of vdde1v2
| C_comp min and max val. don't necessarily correlate with the min and max pvt
| but are the smallest and greatest pad capacitance found.
| var   typ   min   max
C_comp   2.02885pF  2.00670pF  2.05055pF
Vinl = 324.0mV
Vinh = 924.0mV
Vmeas = 600.0mV   | Reference voltage for timing measurements
Cref  = 15.0pF   | Timing specification test load capacitance value
Rref  = 1.0MOhm   | Timing specification test load resistance value
Vref  = 1.2V   | Timing specification test load voltage
[Model Spec]
| TIME_THRESHOLD on pin ZI is "CORE" :
| Rising=50.0% of vdd   Falling=50.0% of vdd
Vinl 420.00000mV 378.00000mV 462.00000mV
Vinh 780.00000mV 702.00000mV 858.00000mV
| variable   typ   min   max
[Temperature Range] 25.0 125.0 -40.0
| variable   typ   min   max
[Voltage Range] 1.2V 1.08V 1.32V
| variable   typ   min   max
[POWER Clamp Reference] 1.2V 1.08V 1.32V
| variable   typ   min   max
[GND Clamp Reference] 0V 0V 0V
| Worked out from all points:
|   slope of the pulldown table from 0 to 0.18 V, typ, clamps not added: 28.3 ohm
|   slope of the pullup table from 0 to 0.18 V, typ, clamps not added: 32.6 ohm
|   GND clamp passes 1 mA (typ) near -0.42 V on its own axis
|   POWER clamp passes 1 mA (typ) near -0.53 V on its own axis
|   rising waveform, R_fixture 50.0, V_fixture 1.2V: 20-80 % time 179ps typ, 215ps min, 166ps max; typ from 0.469 V to 1.2 V
|   falling waveform, R_fixture 50.0, V_fixture 1.2V: 20-80 % time 1.6ns typ, 3.9ns min, 696ps max; typ from 1.2 V to 0.469 V
|   rising waveform, R_fixture 50.0, V_fixture 0V: 20-80 % time 1.36ns typ, 2.91ns min, 604ps max; typ from 0 V to 0.658 V
|   falling waveform, R_fixture 50.0, V_fixture 0V: 20-80 % time 222ps typ, 299ps min, 191ps max; typ from 0.658 V to 0 V
[POWER Clamp]
-1.2V     82.47mA    102.2mA    75.29mA
-950mV    29.35mA    49.08mA    22.16mA
-920mV    22.97mA    42.71mA    17.94mA
-870mV    13.26mA    32.08mA    14.19mA
-830mV    9.388mA    23.58mA    11.94mA
-790mV    7.28mA     15.08mA    9.891mA
-760mV    6.153mA    10.18mA    8.467mA
-710mV    4.618mA    5.741mA    6.312mA
-650mV    3.105mA    3.261mA    4.124mA
-520mV    918uA      1.114mA    1.041mA
-370mV    66.09uA    190.5uA    36.14uA
2.4V      0A         0A         0A
[GND Clamp]
-1.2V     -92.79mA   -113.4mA   -86.23mA
-920mV    -33.29mA   -53.93mA   -27.01mA
-890mV    -26.92mA   -47.56mA   -23.57mA
-840mV    -16.83mA   -36.93mA   -20.11mA
-800mV    -12.88mA   -28.43mA   -17.73mA
-720mV    -9.099mA   -11.98mA   -13.24mA
-680mV    -7.622mA   -7.471mA   -11.12mA
-620mV    -5.599mA   -4.428mA   -8.161mA
-470mV    -1.717mA   -1.41mA    -2.413mA
-410mV    -792.7uA   -748.8uA   -1.042mA
-300mV    -72.27uA   -128.2uA   -61.83uA
2.4V      12.46nA    838.5nA    861.8pA
| variable   typ   min   max
[Pullup Reference] 1.2V 1.08V 1.32V
| variable   typ   min   max
[Pulldown Reference] 0V 0V 0V
[Pullup]
-1.2V     26.81mA    15.8mA     41.46mA
-950mV    26.81mA    15.8mA     41.46mA
-790mV    25.08mA    15.8mA     38.02mA
-650mV    21.98mA    13.75mA    33.69mA
-470mV    16.63mA    10.38mA    25.77mA
-70mV     2.351mA    1.434mA    3.76mA
210mV     -6.364mA   -3.698mA   -10.51mA
440mV     -11.57mA   -6.373mA   -19.77mA
660mV     -14.48mA   -7.626mA   -25.58mA
890mV     -15.9mA    -8.181mA   -28.72mA
1.2V      -16.7mA    -8.508mA   -30.5mA
2.4V      -17.04mA   -8.57mA    -31.41mA
[Pulldown]
-1.2V     -23.48mA   -14.15mA   -35.71mA
-850mV    -23.43mA   -14.15mA   -34.92mA
-690mV    -21.45mA   -13.65mA   -32.45mA
-510mV    -17.98mA   -11.29mA   -27.62mA
-340mV    -12.87mA   -8.023mA   -19.98mA
100mV     3.618mA    2.177mA    5.777mA
320mV     10.79mA    6.261mA    17.52mA
500mV     15.24mA    8.458mA    25.2mA
680mV     17.81mA    9.477mA    30.07mA
830mV     18.75mA    9.817mA    32.02mA
1.11V     19.39mA    10.08mA    33.31mA
2.4V      19.74mA    10.19mA    34.04mA
[Ramp]
dV/dt_r 394.91253mV/1.36026ns 232.18996mV/2.90667ns 551.83145mV/604.01114ps
dV/dt_f 438.40185mV/1.59548ns 277.0515mV/3.90015ns 578.00897mV/696.22329ps
R_load = 50.0
| Removed startup time: 0s 0s 0s  .
| Removed end time: 10.0ns.
[Rising Waveform]
R_fixture   = 50.0
V_fixture   = 1.2V
V_fixture_min = 1.08V
V_fixture_max = 1.32V
0s        469.3mV    618.2mV    356.7mV
256ps     469.3mV    618.2mV    363.3mV
306ps     468.8mV    618.3mV    477.5mV
372ps     465.1mV    618.2mV    801.9mV
468ps     667.4mV    619mV      1.093V
612ps     1.031V     604.8mV    1.24V
888ps     1.172V     959.9mV    1.307V
1.104ns   1.188V     1.052V     1.316V
1.586ns   1.197V     1.075V     1.319V
10ns      1.2V       1.08V      1.32V
| Removed startup time: 0s 0s 0s  .
| Removed end time: 50.0ns.
[Falling Waveform]
R_fixture   = 50.0
V_fixture   = 1.2V
V_fixture_min = 1.08V
V_fixture_max = 1.32V
0s        1.2V       1.08V      1.32V
700ps     1.208V     1.085V     1.288V
1.52ns    1.115V     1.081V     622.2mV
1.81ns    1.033V     1.078V     473.3mV
2.93ns    698.2mV    1.029V     374.1mV
3.74ns    563.3mV    963mV      363.6mV
4.87ns    503.6mV    863mV      358.9mV
7.41ns    475.9mV    708.6mV    356.8mV
10.63ns   470.4mV    642.2mV    356.6mV
50ns      469.3mV    618.2mV    356.7mV
| Removed startup time: 0s 0s 0s  .
| Removed end time: 50.0ns.
[Rising Waveform]
R_fixture   = 50.0
V_fixture   = 0V
V_fixture_min = 0V
V_fixture_max = 0V
0s        10.51nV    645.8nV    6.268nV
730ps     -4.769mV   -3.49mV    35.99mV
910ps     -1.877mV   -4.527mV   161.8mV
1.39ns    54.4mV     -1.248mV   639.4mV
1.71ns    151.4mV    1.718mV    804.7mV
2.87ns    502.1mV    62.71mV    909.1mV
3.82ns    603.7mV    157.8mV    917mV
5.75ns    648.4mV    301.2mV    919.5mV
9.41ns    657.5mV    374.6mV    919.8mV
50ns      658.2mV    387mV      919.7mV
| Removed startup time: 0s 0s 0s  .
| Removed end time: 10.0ns.
[Falling Waveform]
R_fixture   = 50.0
V_fixture   = 0V
V_fixture_min = 0V
V_fixture_max = 0V
0s        658.2mV    387mV      919.7mV
220ps     657.8mV    387mV      928.9mV
322ps     674.1mV    387mV      677.1mV
418ps     513.2mV    393.8mV    344.3mV
508ps     314mV      410.6mV    168.8mV
644ps     122.2mV    291.3mV    61.21mV
836ps     33.71mV    124.7mV    9.864mV
1.088ns   8.021mV    31.22mV    1.222mV
1.56ns    1.041mV    3.251mV    379.8uV
10ns      2.406uV    26.42uV    150.2nV
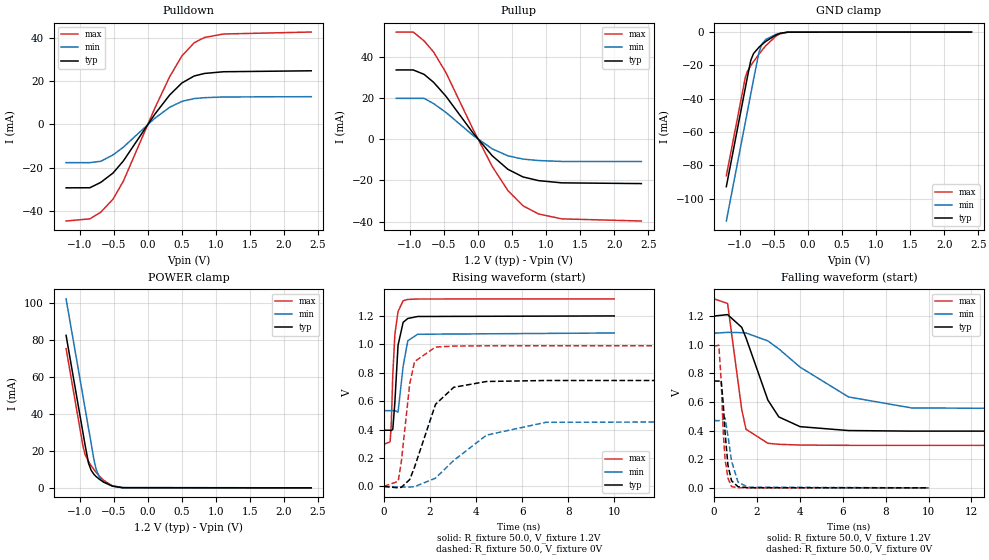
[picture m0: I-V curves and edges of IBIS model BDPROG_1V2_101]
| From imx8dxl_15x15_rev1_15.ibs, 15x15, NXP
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[Model] BDPROG_1V2_101
Model_type I/O
Polarity   Non-Inverting
Enable   Active-Low
| CAP_THRESHOLD on pad IO is "CMOS" :
| Rising=10.0% of vdde1v2   Falling=90.0% of vdde1v2
| C_comp min and max val. don't necessarily correlate with the min and max pvt
| but are the smallest and greatest pad capacitance found.
| var   typ   min   max
C_comp   2.02780pF  2.00555pF  2.04970pF
Vinl = 324.0mV
Vinh = 924.0mV
Vmeas = 600.0mV   | Reference voltage for timing measurements
Cref  = 15.0pF   | Timing specification test load capacitance value
Rref  = 1.0MOhm   | Timing specification test load resistance value
Vref  = 1.2V   | Timing specification test load voltage
[Model Spec]
| TIME_THRESHOLD on pin ZI is "CORE" :
| Rising=50.0% of vdd   Falling=50.0% of vdd
Vinl 420.00000mV 378.00000mV 462.00000mV
Vinh 780.00000mV 702.00000mV 858.00000mV
| variable   typ   min   max
[Temperature Range] 25.0 125.0 -40.0
| variable   typ   min   max
[Voltage Range] 1.2V 1.08V 1.32V
| variable   typ   min   max
[POWER Clamp Reference] 1.2V 1.08V 1.32V
| variable   typ   min   max
[GND Clamp Reference] 0V 0V 0V
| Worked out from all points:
|   slope of the pulldown table from 0 to 0.18 V, typ, clamps not added: 22.6 ohm
|   slope of the pullup table from 0 to 0.18 V, typ, clamps not added: 25.9 ohm
|   GND clamp passes 1 mA (typ) near -0.42 V on its own axis
|   POWER clamp passes 1 mA (typ) near -0.53 V on its own axis
|   rising waveform, R_fixture 50.0, V_fixture 1.2V: 20-80 % time 181ps typ, 221ps min, 168ps max; typ from 0.396 V to 1.2 V
|   falling waveform, R_fixture 50.0, V_fixture 1.2V: 20-80 % time 1.19ns typ, 3.11ns min, 520ps max; typ from 1.2 V to 0.396 V
|   rising waveform, R_fixture 50.0, V_fixture 0V: 20-80 % time 954ps typ, 2.16ns min, 416ps max; typ from 0 V to 0.746 V
|   falling waveform, R_fixture 50.0, V_fixture 0V: 20-80 % time 231ps typ, 323ps min, 195ps max; typ from 0.746 V to 0 V
[POWER Clamp]
-1.2V     82.47mA    102.2mA    75.29mA
-950mV    29.35mA    49.08mA    22.16mA
-920mV    22.97mA    42.71mA    17.94mA
-870mV    13.26mA    32.08mA    14.19mA
-830mV    9.388mA    23.58mA    11.94mA
-790mV    7.28mA     15.08mA    9.891mA
-760mV    6.153mA    10.18mA    8.467mA
-710mV    4.618mA    5.741mA    6.312mA
-650mV    3.105mA    3.261mA    4.124mA
-520mV    918uA      1.114mA    1.041mA
-370mV    66.09uA    190.5uA    36.14uA
2.4V      0A         0A         0A
[GND Clamp]
-1.2V     -92.79mA   -113.4mA   -86.23mA
-920mV    -33.29mA   -53.93mA   -27.01mA
-890mV    -26.92mA   -47.56mA   -23.57mA
-840mV    -16.83mA   -36.93mA   -20.11mA
-800mV    -12.88mA   -28.43mA   -17.73mA
-720mV    -9.099mA   -11.98mA   -13.24mA
-680mV    -7.622mA   -7.471mA   -11.12mA
-620mV    -5.599mA   -4.428mA   -8.161mA
-470mV    -1.717mA   -1.41mA    -2.413mA
-410mV    -792.7uA   -748.8uA   -1.042mA
-300mV    -72.27uA   -128.2uA   -61.83uA
2.4V      12.46nA    838.5nA    861.8pA
| variable   typ   min   max
[Pullup Reference] 1.2V 1.08V 1.32V
| variable   typ   min   max
[Pulldown Reference] 0V 0V 0V
[Pullup]
-1.2V     33.68mA    19.87mA    52.11mA
-950mV    33.68mA    19.87mA    52.11mA
-790mV    31.52mA    19.87mA    47.79mA
-650mV    27.64mA    17.29mA    42.35mA
-470mV    20.92mA    13.06mA    32.41mA
-70mV     2.96mA     1.806mA    4.73mA
210mV     -8.02mA    -4.665mA   -13.23mA
440mV     -14.61mA   -8.052mA   -24.94mA
660mV     -18.3mA    -9.645mA   -32.31mA
890mV     -20.12mA   -10.35mA   -36.32mA
1.23V     -21.2mA    -10.79mA   -38.71mA
2.4V      -21.56mA   -10.85mA   -39.75mA
[Pulldown]
-1.2V     -29.33mA   -17.69mA   -44.64mA
-850mV    -29.28mA   -17.69mA   -43.64mA
-690mV    -26.8mA    -17.06mA   -40.55mA
-510mV    -22.47mA   -14.12mA   -34.51mA
-360mV    -16.96mA   -10.58mA   -26.31mA
100mV     4.522mA    2.722mA    7.22mA
320mV     13.49mA    7.831mA    21.9mA
500mV     19.07mA    10.58mA    31.51mA
680mV     22.28mA    11.86mA    37.61mA
830mV     23.46mA    12.28mA    40.06mA
1.11V     24.26mA    12.62mA    41.68mA
2.4V      24.7mA     12.75mA    42.59mA
[Ramp]
dV/dt_r 447.6031mV/953.99318ps 281.83258mV/2.1587ns 593.94676mV/416.04379ps
dV/dt_f 482.68615mV/1.19161ns 327.73628mV/3.10839ns 613.97263mV/520.07254ps
R_load = 50.0
| Removed startup time: 0s 0s 0s  .
| Removed end time: 10.0ns.
[Rising Waveform]
R_fixture   = 50.0
V_fixture   = 1.2V
V_fixture_min = 1.08V
V_fixture_max = 1.32V
0s        395.5mV    533.8mV    296.7mV
268ps     395.6mV    533.8mV    314.6mV
318ps     393.4mV    533.8mV    435.6mV
384ps     401.5mV    533.7mV    783.6mV
474ps     592.3mV    534.5mV    1.069V
612ps     993.2mV    522.9mV    1.231V
834ps     1.155V     846.2mV    1.307V
1.036ns   1.182V     1.025V     1.316V
1.464ns   1.196V     1.071V     1.319V
10ns      1.2V       1.08V      1.32V
| Removed startup time: 0s 0s 0s  .
| Removed end time: 50.0ns.
[Falling Waveform]
R_fixture   = 50.0
V_fixture   = 1.2V
V_fixture_min = 1.08V
V_fixture_max = 1.32V
0s        1.2V       1.08V      1.32V
630ps     1.21V      1.086V     1.288V
1.29ns    1.121V     1.084V     546.6mV
1.49ns    1.047V     1.082V     409.1mV
2.51ns    612.8mV    1.026V     311.3mV
3.02ns    495.3mV    970.6mV    304.1mV
4.01ns    427.4mV    843.2mV    299mV
6.27ns    400.2mV    634.9mV    296.9mV
9.22ns    396.2mV    558mV      296.7mV
50ns      395.5mV    533.8mV    296.7mV
| Removed startup time: 0s 0s 0s  .
| Removed end time: 50.0ns.
[Rising Waveform]
R_fixture   = 50.0
V_fixture   = 0V
V_fixture_min = 0V
V_fixture_max = 0V
0s        8.54nV     531.6nV    5.193nV
620ps     -9.764mV   -2.289mV   36.15mV
760ps     -5.598mV   -3.924mV   180.4mV
1.12ns    48.8mV     -4.009mV   723.2mV
1.33ns    136.7mV    -1.393mV   879mV
2.24ns    578mV      58.61mV    980.8mV
3.03ns    697.6mV    183.3mV    987.9mV
4.45ns    738.6mV    361mV      989.7mV
7.03ns    745.6mV    451.3mV    990mV
50ns      746mV      469.7mV    989.9mV
| Removed startup time: 0s 0s 0s  .
| Removed end time: 10.0ns.
[Falling Waveform]
R_fixture   = 50.0
V_fixture   = 0V
V_fixture_min = 0V
V_fixture_max = 0V
0s        746mV      469.7mV    989.9mV
222ps     745.7mV    469.7mV    996mV
330ps     751.6mV    469.6mV    752.4mV
430ps     583.1mV    479.2mV    382.5mV
512ps     386.5mV    488mV      200.6mV
648ps     157.2mV    361.3mV    67.34mV
814ps     49.71mV    187.6mV    8.812mV
1.114ns   8.141mV    40.57mV    948.5uV
1.572ns   944.9uV    4.688mV    357.3uV
10ns      1.369uV    19.83uV    102.1nV
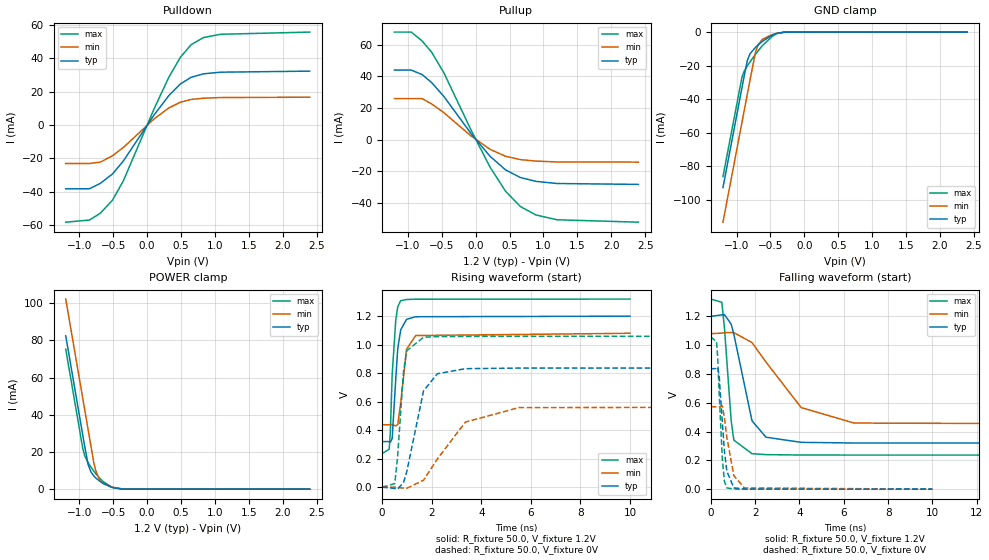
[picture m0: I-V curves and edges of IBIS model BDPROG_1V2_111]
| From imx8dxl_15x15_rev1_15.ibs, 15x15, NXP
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[Model] BDPROG_1V2_111
Model_type I/O
Polarity   Non-Inverting
Enable   Active-Low
| CAP_THRESHOLD on pad IO is "CMOS" :
| Rising=10.0% of vdde1v2   Falling=90.0% of vdde1v2
| C_comp min and max val. don't necessarily correlate with the min and max pvt
| but are the smallest and greatest pad capacitance found.
| var   typ   min   max
C_comp   2.02600pF  2.00375pF  2.04830pF
Vinl = 324.0mV
Vinh = 924.0mV
Vmeas = 600.0mV   | Reference voltage for timing measurements
Cref  = 15.0pF   | Timing specification test load capacitance value
Rref  = 1.0MOhm   | Timing specification test load resistance value
Vref  = 1.2V   | Timing specification test load voltage
[Model Spec]
| TIME_THRESHOLD on pin ZI is "CORE" :
| Rising=50.0% of vdd   Falling=50.0% of vdd
Vinl 420.00000mV 378.00000mV 462.00000mV
Vinh 780.00000mV 702.00000mV 858.00000mV
| variable   typ   min   max
[Temperature Range] 25.0 125.0 -40.0
| variable   typ   min   max
[Voltage Range] 1.2V 1.08V 1.32V
| variable   typ   min   max
[POWER Clamp Reference] 1.2V 1.08V 1.32V
| variable   typ   min   max
[GND Clamp Reference] 0V 0V 0V
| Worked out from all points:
|   slope of the pulldown table from 0 to 0.18 V, typ, clamps not added: 17.3 ohm
|   slope of the pullup table from 0 to 0.18 V, typ, clamps not added: 19.7 ohm
|   GND clamp passes 1 mA (typ) near -0.43 V on its own axis
|   POWER clamp passes 1 mA (typ) near -0.53 V on its own axis
|   rising waveform, R_fixture 50.0, V_fixture 1.2V: 20-80 % time 185ps typ, 230ps min, 164ps max; typ from 0.32 V to 1.2 V
|   falling waveform, R_fixture 50.0, V_fixture 1.2V: 20-80 % time 699ps typ, 1.88ns min, 308ps max; typ from 1.2 V to 0.32 V
|   rising waveform, R_fixture 50.0, V_fixture 0V: 20-80 % time 589ps typ, 1.42ns min, 260ps max; typ from 0 V to 0.836 V
|   falling waveform, R_fixture 50.0, V_fixture 0V: 20-80 % time 243ps typ, 352ps min, 188ps max; typ from 0.836 V to 0 V
[POWER Clamp]
-1.2V     82.47mA    102.2mA    75.29mA
-950mV    29.35mA    49.08mA    22.16mA
-920mV    22.97mA    42.71mA    17.94mA
-870mV    13.26mA    32.08mA    14.19mA
-830mV    9.388mA    23.58mA    11.94mA
-790mV    7.28mA     15.08mA    9.891mA
-760mV    6.153mA    10.18mA    8.467mA
-710mV    4.618mA    5.741mA    6.312mA
-650mV    3.105mA    3.261mA    4.124mA
-520mV    918uA      1.114mA    1.041mA
-370mV    66.09uA    190.5uA    36.14uA
2.4V      0A         0A         0A
[GND Clamp]
-1.2V     -92.79mA   -113.4mA   -86.23mA
-920mV    -33.29mA   -53.93mA   -27.01mA
-890mV    -26.92mA   -47.56mA   -23.57mA
-840mV    -16.83mA   -36.93mA   -20.11mA
-800mV    -12.88mA   -28.43mA   -17.73mA
-720mV    -9.099mA   -11.98mA   -13.24mA
-680mV    -7.622mA   -7.471mA   -11.12mA
-620mV    -5.599mA   -4.428mA   -8.161mA
-470mV    -1.717mA   -1.41mA    -2.413mA
-400mV    -678.8uA   -662.4uA   -876.2uA
-300mV    -72.27uA   -128.2uA   -61.83uA
2.4V      12.46nA    838.5nA    861.8pA
| variable   typ   min   max
[Pullup Reference] 1.2V 1.08V 1.32V
| variable   typ   min   max
[Pulldown Reference] 0V 0V 0V
[Pullup]
-1.2V     44.03mA    25.98mA    68.12mA
-950mV    44.03mA    25.98mA    68.12mA
-790mV    41.21mA    25.98mA    62.49mA
-650mV    36.14mA    22.62mA    55.39mA
-470mV    27.37mA    17.09mA    42.39mA
-70mV     3.875mA    2.367mA    6.19mA
210mV     -10.51mA   -6.124mA   -17.33mA
440mV     -19.18mA   -10.59mA   -32.71mA
660mV     -24.07mA   -12.7mA    -42.46mA
890mV     -26.48mA   -13.63mA   -47.79mA
1.2V      -27.84mA   -14.18mA   -50.81mA
2.4V      -28.4mA    -14.29mA   -52.35mA
[Pulldown]
-1.2V     -38.22mA   -23.03mA   -58.2mA
-850mV    -38.16mA   -23.03mA   -56.9mA
-690mV    -34.93mA   -22.24mA   -52.85mA
-510mV    -29.29mA   -18.4mA    -44.98mA
-350mV    -21.54mA   -13.44mA   -33.43mA
100mV     5.897mA    3.552mA    9.411mA
320mV     17.6mA     10.23mA    28.56mA
490mV     24.57mA    13.68mA    40.54mA
650mV     28.63mA    15.33mA    48.15mA
830mV     30.67mA    16.06mA    52.37mA
1.08V     31.66mA    16.47mA    54.37mA
2.4V      32.3mA     16.68mA    55.69mA
[Ramp]
dV/dt_r 501.51073mV/589.03692ps 343.04529mV/1.41817ns 635.10007mV/259.7302ps
dV/dt_f 528.08116mV/698.74778ps 384.95258mV/1.88086ns 650.17523mV/307.75592ps
R_load = 50.0
| Removed startup time: 0s 0s 0s  .
| Removed end time: 10.0ns.
[Rising Waveform]
R_fixture   = 50.0
V_fixture   = 1.2V
V_fixture_min = 1.08V
V_fixture_max = 1.32V
0s        319.9mV    438.4mV    236.8mV
284ps     320.1mV    438.4mV    266.7mV
330ps     316.5mV    438.4mV    384mV
404ps     340.6mV    438.4mV    786.8mV
550ps     759.7mV    430.4mV    1.173V
630ps     972.4mV    439.5mV    1.266V
750ps     1.105V     593.3mV    1.309V
986ps     1.178V     968.7mV    1.317V
1.354ns   1.196V     1.064V     1.319V
10ns      1.2V       1.08V      1.32V
| Removed startup time: 0s 0s 0s  .
| Removed end time: 50.0ns.
[Falling Waveform]
R_fixture   = 50.0
V_fixture   = 1.2V
V_fixture_min = 1.08V
V_fixture_max = 1.32V
0s        1.2V       1.08V      1.32V
500ps     1.21V      1.083V     1.298V
620ps     1.212V     1.087V     1.116V
920ps     1.146V     1.087V     478.1mV
1.04ns    1.077V     1.087V     340.6mV
1.86ns    475mV      1.018V     246.4mV
2.49ns    360.9mV    883.1mV    239.9mV
4.08ns    325.1mV    566.5mV    237mV
6.47ns    320.5mV    459mV      236.7mV
50ns      319.9mV    438.4mV    236.8mV
| Removed startup time: 0s 0s 0s  .
| Removed end time: 50.0ns.
[Rising Waveform]
R_fixture   = 50.0
V_fixture   = 0V
V_fixture_min = 0V
V_fixture_max = 0V
0s        6.413nV    400.8nV    4.086nV
510ps     -8.507mV   621uV      25.4mV
620ps     -13.71mV   -2.177mV   205.1mV
860ps     31.86mV    -5.986mV   807.4mV
990ps     105.7mV    -7.824mV   957mV
1.67ns    676mV      49.24mV    1.052V
2.23ns    796mV      198.8mV    1.057V
3.36ns    831.7mV    457mV      1.058V
5.51ns    835.7mV    558.3mV    1.059V
50ns      835.9mV    571.7mV    1.058V
| Removed startup time: 0s 0s 0s  .
| Removed end time: 10.0ns.
[Falling Waveform]
R_fixture   = 50.0
V_fixture   = 0V
V_fixture_min = 0V
V_fixture_max = 0V
0s        835.8mV    571.7mV    1.058V
262ps     837.7mV    571.8mV    1.023V
316ps     845.6mV    571.8mV    907.9mV
380ps     784.2mV    571.3mV    667.9mV
522ps     465.9mV    579.2mV    213.9mV
616ps     264.3mV    496.9mV    53.31mV
726ps     124.7mV    359.7mV    8.43mV
1.042ns   9.067mV    93.4mV     883.7uV
1.514ns   895.9uV    8.678mV    260.6uV
10ns      205.1nV    6.519uV    52.41nV
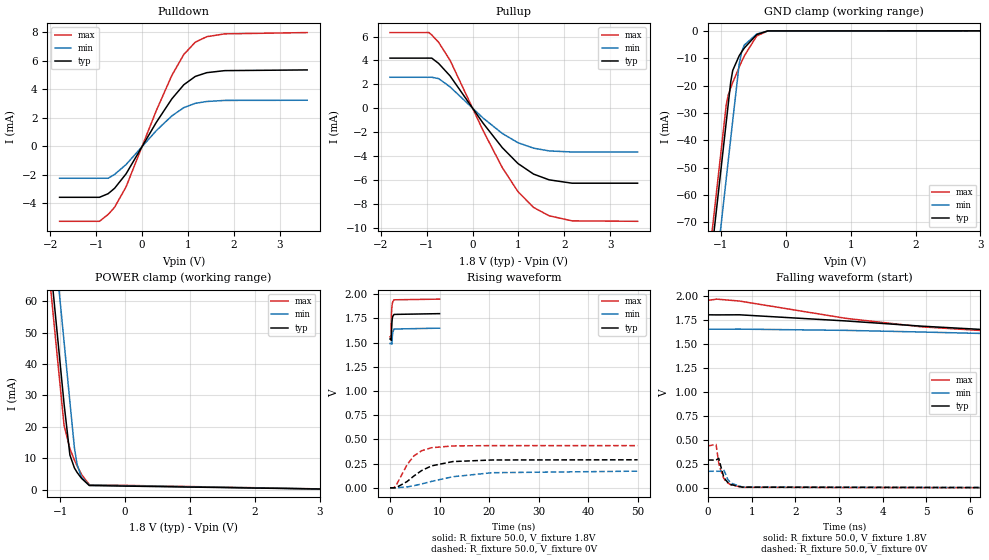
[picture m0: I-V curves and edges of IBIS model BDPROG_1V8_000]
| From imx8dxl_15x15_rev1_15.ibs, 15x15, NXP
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[Model] BDPROG_1V8_000
Model_type I/O
Polarity   Non-Inverting
Enable   Active-Low
| CAP_THRESHOLD on pad IO is "CMOS" :
| Rising=10.0% of vdde1v8   Falling=90.0% of vdde1v8
| C_comp min and max val. don't necessarily correlate with the min and max pvt
| but are the smallest and greatest pad capacitance found.
| var   typ   min   max
C_comp   2.02015pF  1.99540pF  2.04410pF
Vinl = 577.5mV
Vinh = 1.2675V
Vmeas = 900.0mV   | Reference voltage for timing measurements
Cref  = 15.0pF   | Timing specification test load capacitance value
Rref  = 1.0MOhm   | Timing specification test load resistance value
Vref  = 1.8V   | Timing specification test load voltage
[Model Spec]
| TIME_THRESHOLD on pin ZI is "CORE" :
| Rising=50.0% of vdd   Falling=50.0% of vdd
Vinl 630.00000mV 577.50000mV 682.50000mV
Vinh 1.17000V 1.07250V 1.26750V
| variable   typ   min   max
[Temperature Range] 25.0 125.0 -40.0
| variable   typ   min   max
[Voltage Range] 1.8V 1.65V 1.95V
| variable   typ   min   max
[POWER Clamp Reference] 1.8V 1.65V 1.95V
| variable   typ   min   max
[GND Clamp Reference] 0V 0V 0V
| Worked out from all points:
|   slope of the pulldown table from 0 to 0.27 V, typ, clamps not added: 184 ohm
|   slope of the pullup table from 0 to 0.27 V, typ, clamps not added: 186 ohm
|   GND clamp passes 1 mA (typ) near -0.42 V on its own axis
|   POWER clamp passes 1 mA (typ) near -0.53 V on its own axis
|   rising waveform, R_fixture 50.0, V_fixture 1.8V: 20-80 % time 162ps typ, 161ps min, 164ps max; typ from 1.54 V to 1.8 V
|   falling waveform, R_fixture 50.0, V_fixture 1.8V: 20-80 % time 6.69ns typ, 11.5ns min, 4.35ns max; typ from 1.8 V to 1.54 V
|   rising waveform, R_fixture 50.0, V_fixture 0V: 20-80 % time 5.38ns typ, 9.99ns min, 3.35ns max; typ from 0 V to 0.289 V
|   falling waveform, R_fixture 50.0, V_fixture 0V: 20-80 % time 166ps typ, 168ps min, 165ps max; typ from 0.289 V to 0 V
[POWER Clamp]
-1.8V     210.1mA    229.8mA    202.8mA
-1.21V    84.68mA    104.4mA    77.47mA
-1.18V    78.31mA    98.07mA    71.09mA
-1.15V    71.93mA    91.7mA     64.72mA
-1.06V    52.81mA    72.57mA    45.59mA
-940mV    27.31mA    47.07mA    20.48mA
-850mV    11.02mA    27.95mA    13.03mA
-780mV    6.883mA    13.28mA    9.41mA
-740mV    5.505mA    8.047mA    7.575mA
-670mV    3.576mA    3.902mA    4.805mA
-550mV    1.291mA    1.449mA    1.548mA
3.6V      0A         0A         0A
[GND Clamp]
-1.8V     -220.4mA   -241.1mA   -213.8mA
-920mV    -33.4mA    -54.08mA   -27.05mA
-890mV    -27.02mA   -47.71mA   -23.58mA
-850mV    -18.55mA   -39.21mA   -20.74mA
-820mV    -14.49mA   -32.83mA   -18.91mA
-720mV    -9.101mA   -12.08mA   -13.24mA
-680mV    -7.624mA   -7.509mA   -11.13mA
-640mV    -6.25mA    -5.182mA   -9.119mA
-450mV    -1.363mA   -1.162mA   -1.887mA
-280mV    -38.48uA   -82.86uA   -27.73uA
3.6V      43.32nA    1.229uA    123.6nA
| variable   typ   min   max
[Pullup Reference] 1.8V 1.65V 1.95V
| variable   typ   min   max
[Pulldown Reference] 0V 0V 0V
[Pullup]
-1.8V     4.195mA    2.596mA    6.33mA
-950mV    4.195mA    2.596mA    6.33mA
-890mV    4.195mA    2.596mA    6.13mA
-740mV    3.753mA    2.484mA    5.519mA
-490mV    2.707mA    1.792mA    4.011mA
230mV     -1.241mA   -812.8uA   -1.861mA
650mV     -3.29mA    -2.104mA   -4.959mA
990mV     -4.609mA   -2.87mA    -6.956mA
1.33V     -5.492mA   -3.327mA   -8.277mA
1.67V     -5.973mA   -3.557mA   -8.976mA
2.17V     -6.255mA   -3.647mA   -9.401mA
3.6V      -6.255mA   -3.647mA   -9.437mA
[Pulldown]
-1.8V     -3.584mA   -2.246mA   -5.27mA
-930mV    -3.584mA   -2.246mA   -5.27mA
-740mV    -3.328mA   -2.246mA   -4.787mA
-600mV    -2.95mA    -1.976mA   -4.284mA
-350mV    -1.937mA   -1.286mA   -2.85mA
310mV     1.683mA    1.099mA    2.51mA
650mV     3.338mA    2.14mA     4.989mA
910mV     4.323mA    2.714mA    6.453mA
1.16V     4.908mA    3.018mA    7.314mA
1.41V     5.171mA    3.146mA    7.698mA
1.8V      5.314mA    3.222mA    7.897mA
3.6V      5.364mA    3.234mA    7.988mA
[Ramp]
dV/dt_r 173.69808mV/5.38459ns 103.36712mV/9.98651ns 261.6153mV/3.34628ns
dV/dt_f 157.15879mV/6.6879ns 94.92039mV/11.51674ns 234.17767mV/4.34911ns
R_load = 50.0
| Removed startup time: 0s 0s 0s  .
| Removed end time: 10.0ns.
[Rising Waveform]
R_fixture   = 50.0
V_fixture   = 1.8V
V_fixture_min = 1.65V
V_fixture_max = 1.95V
0s        1.538V     1.491V     1.56V
192ps     1.538V     1.492V     1.548V
258ps     1.524V     1.491V     1.729V
282ps     1.562V     1.491V     1.772V
334ps     1.655V     1.491V     1.835V
398ps     1.717V     1.485V     1.879V
468ps     1.752V     1.561V     1.905V
544ps     1.771V     1.604V     1.921V
806ps     1.792V     1.641V     1.943V
10ns      1.8V       1.65V      1.95V
| Removed startup time: 0s 0s 0s  .
| Removed end time: 50.0ns.
[Falling Waveform]
R_fixture   = 50.0
V_fixture   = 1.8V
V_fixture_min = 1.65V
V_fixture_max = 1.95V
0s        1.8V       1.65V      1.95V
200ps     1.799V     1.65V      1.963V
720ps     1.8V       1.651V     1.943V
3.16ns    1.736V     1.638V     1.763V
4.89ns    1.682V     1.621V     1.675V
6.89ns    1.632V     1.599V     1.619V
9.5ns     1.59V      1.572V     1.585V
14.6ns    1.555V     1.534V     1.564V
22.74ns   1.541V     1.506V     1.56V
50ns      1.538V     1.492V     1.56V
| Removed startup time: 0s 0s 0s  .
| Removed end time: 50.0ns.
[Rising Waveform]
R_fixture   = 50.0
V_fixture   = 0V
V_fixture_min = 0V
V_fixture_max = 0V
0s        417.2nV    1.675uV    902.2nV
740ps     -424.3uV   -484.7uV   660.3uV
1.2ns     822.5uV    -142.9uV   22.41mV
3.42ns    63.83mV    8.988mV    237mV
4.81ns    121.9mV    21.65mV    328.6mV
6.36ns    177.6mV    39.92mV    383mV
8.38ns    226.7mV    66.39mV    414.3mV
12.68ns   271.3mV    114.6mV    432.8mV
20.6ns    287.6mV    156.1mV    436.2mV
50ns      289.5mV    172.3mV    436mV
| Removed startup time: 0s 0s 0s  .
| Removed end time: 10.0ns.
[Falling Waveform]
R_fixture   = 50.0
V_fixture   = 0V
V_fixture_min = 0V
V_fixture_max = 0V
0s        289.5mV    172.4mV    436mV
182ps     289.1mV    172.4mV    452.5mV
244ps     307.5mV    172.5mV    260.1mV
268ps     263.6mV    172mV      210.1mV
354ps     120.4mV    190.9mV    105.2mV
388ps     91.61mV    157.4mV    80.65mV
446ps     58.79mV    91.59mV    53.12mV
518ps     35.02mV    50.1mV     32.18mV
780ps     7.178mV    9.37mV     5.561mV
10ns      13.23uV    19.9uV     8.195uV
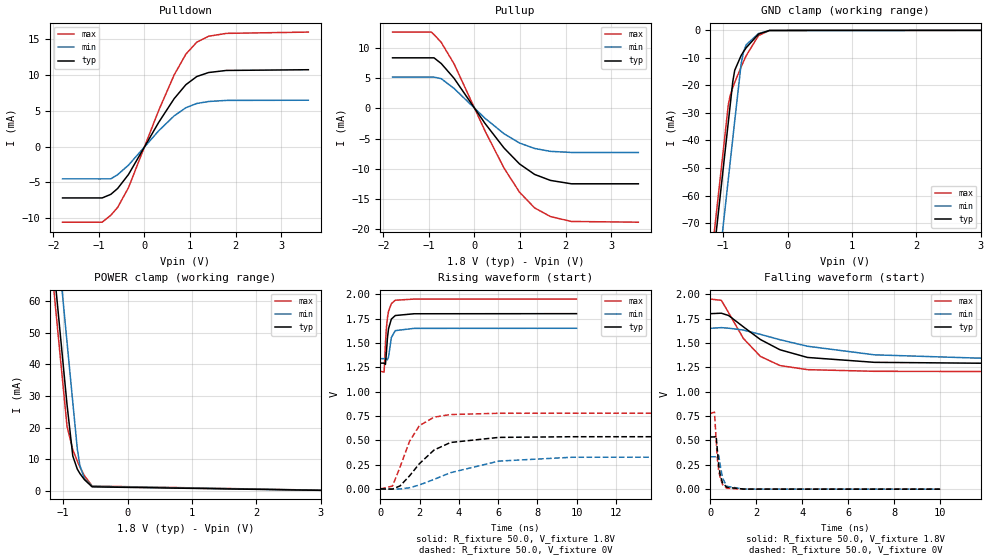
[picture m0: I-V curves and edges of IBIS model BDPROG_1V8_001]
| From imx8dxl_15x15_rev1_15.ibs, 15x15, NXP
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[Model] BDPROG_1V8_001
Model_type I/O
Polarity   Non-Inverting
Enable   Active-Low
| CAP_THRESHOLD on pad IO is "CMOS" :
| Rising=10.0% of vdde1v8   Falling=90.0% of vdde1v8
| C_comp min and max val. don't necessarily correlate with the min and max pvt
| but are the smallest and greatest pad capacitance found.
| var   typ   min   max
C_comp   2.01995pF  1.99505pF  2.04395pF
Vinl = 577.5mV
Vinh = 1.2675V
Vmeas = 900.0mV   | Reference voltage for timing measurements
Cref  = 15.0pF   | Timing specification test load capacitance value
Rref  = 1.0MOhm   | Timing specification test load resistance value
Vref  = 1.8V   | Timing specification test load voltage
[Model Spec]
| TIME_THRESHOLD on pin ZI is "CORE" :
| Rising=50.0% of vdd   Falling=50.0% of vdd
Vinl 630.00000mV 577.50000mV 682.50000mV
Vinh 1.17000V 1.07250V 1.26750V
| variable   typ   min   max
[Temperature Range] 25.0 125.0 -40.0
| variable   typ   min   max
[Voltage Range] 1.8V 1.65V 1.95V
| variable   typ   min   max
[POWER Clamp Reference] 1.8V 1.65V 1.95V
| variable   typ   min   max
[GND Clamp Reference] 0V 0V 0V
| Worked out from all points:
|   slope of the pulldown table from 0 to 0.27 V, typ, clamps not added: 91.8 ohm
|   slope of the pullup table from 0 to 0.27 V, typ, clamps not added: 93.2 ohm
|   GND clamp passes 1 mA (typ) near -0.42 V on its own axis
|   POWER clamp passes 1 mA (typ) near -0.53 V on its own axis
|   rising waveform, R_fixture 50.0, V_fixture 1.8V: 20-80 % time 166ps typ, 170ps min, 165ps max; typ from 1.29 V to 1.8 V
|   falling waveform, R_fixture 50.0, V_fixture 1.8V: 20-80 % time 2.19ns typ, 3.86ns min, 1.4ns max; typ from 1.8 V to 1.29 V
|   rising waveform, R_fixture 50.0, V_fixture 0V: 20-80 % time 1.6ns typ, 3.02ns min, 979ps max; typ from 0 V to 0.536 V
|   falling waveform, R_fixture 50.0, V_fixture 0V: 20-80 % time 168ps typ, 182ps min, 164ps max; typ from 0.536 V to 0 V
[POWER Clamp]
-1.8V     210.1mA    229.8mA    202.8mA
-1.21V    84.68mA    104.4mA    77.47mA
-1.18V    78.31mA    98.07mA    71.09mA
-1.15V    71.93mA    91.7mA     64.72mA
-1.06V    52.81mA    72.57mA    45.59mA
-940mV    27.31mA    47.07mA    20.48mA
-850mV    11.02mA    27.95mA    13.03mA
-780mV    6.883mA    13.28mA    9.41mA
-740mV    5.505mA    8.047mA    7.575mA
-670mV    3.576mA    3.902mA    4.805mA
-550mV    1.291mA    1.449mA    1.548mA
3.6V      0A         0A         0A
[GND Clamp]
-1.8V     -220.4mA   -241.1mA   -213.8mA
-920mV    -33.4mA    -54.08mA   -27.05mA
-890mV    -27.02mA   -47.71mA   -23.58mA
-850mV    -18.55mA   -39.21mA   -20.74mA
-820mV    -14.49mA   -32.83mA   -18.91mA
-720mV    -9.101mA   -12.08mA   -13.24mA
-680mV    -7.624mA   -7.509mA   -11.13mA
-640mV    -6.25mA    -5.182mA   -9.119mA
-450mV    -1.363mA   -1.162mA   -1.887mA
-280mV    -38.48uA   -82.86uA   -27.73uA
3.6V      43.32nA    1.229uA    123.6nA
| variable   typ   min   max
[Pullup Reference] 1.8V 1.65V 1.95V
| variable   typ   min   max
[Pulldown Reference] 0V 0V 0V
[Pullup]
-1.8V     8.391mA    5.193mA    12.66mA
-950mV    8.391mA    5.193mA    12.66mA
-890mV    8.391mA    5.193mA    12.26mA
-730mV    7.438mA    4.925mA    10.94mA
-450mV    5.004mA    3.319mA    7.414mA
230mV     -2.481mA   -1.627mA   -3.721mA
650mV     -6.58mA    -4.212mA   -9.919mA
990mV     -9.22mA    -5.747mA   -13.91mA
1.32V     -10.95mA   -6.647mA   -16.5mA
1.67V     -11.95mA   -7.128mA   -17.95mA
2.13V     -12.51mA   -7.31mA    -18.76mA
3.6V      -12.51mA   -7.31mA    -18.88mA
[Pulldown]
-1.8V     -7.158mA   -4.494mA   -10.54mA
-930mV    -7.158mA   -4.494mA   -10.54mA
-740mV    -6.656mA   -4.494mA   -9.574mA
-590mV    -5.838mA   -3.908mA   -8.483mA
-350mV    -3.873mA   -2.572mA   -5.7mA
310mV     3.365mA    2.198mA    5.02mA
650mV     6.677mA    4.282mA    9.978mA
910mV     8.646mA    5.431mA    12.91mA
1.15V     9.784mA    6.024mA    14.58mA
1.41V     10.34mA    6.298mA    15.4mA
1.8V      10.63mA    6.45mA     15.8mA
3.6V      10.73mA    6.474mA    15.98mA
[Ramp]
dV/dt_r 321.54338mV/1.59617ns 199.32805mV/3.01927ns 465.7437mV/978.88359ps
dV/dt_f 304.69244mV/2.19339ns 187.40375mV/3.86041ns 445.21071mV/1.39586ns
R_load = 50.0
| Removed startup time: 0s 0s 0s  .
| Removed end time: 10.0ns.
[Rising Waveform]
R_fixture   = 50.0
V_fixture   = 1.8V
V_fixture_min = 1.65V
V_fixture_max = 1.95V
0s        1.292V     1.338V     1.208V
196ps     1.292V     1.338V     1.201V
264ps     1.28V      1.338V     1.493V
306ps     1.384V     1.338V     1.639V
364ps     1.548V     1.326V     1.756V
420ps     1.645V     1.356V     1.823V
564ps     1.744V     1.555V     1.903V
766ps     1.781V     1.626V     1.938V
1.722ns   1.799V     1.649V     1.95V
10ns      1.8V       1.65V      1.95V
| Removed startup time: 0s 0s 0s  .
| Removed end time: 50.0ns.
[Falling Waveform]
R_fixture   = 50.0
V_fixture   = 1.8V
V_fixture_min = 1.65V
V_fixture_max = 1.95V
0s        1.8V       1.65V      1.95V
480ps     1.805V     1.657V     1.937V
800ps     1.781V     1.651V     1.809V
1.44ns    1.665V     1.632V     1.546V
2.18ns    1.535V     1.588V     1.362V
3.03ns    1.43V      1.533V     1.268V
4.23ns    1.351V     1.466V     1.226V
7.14ns    1.301V     1.378V     1.209V
11.68ns   1.292V     1.344V     1.207V
50ns      1.292V     1.338V     1.208V
| Removed startup time: 0s 0s 0s  .
| Removed end time: 50.0ns.
[Rising Waveform]
R_fixture   = 50.0
V_fixture   = 0V
V_fixture_min = 0V
V_fixture_max = 0V
0s        341nV      1.402uV    694.7nV
620ps     -1.688mV   -2.496mV   29.12mV
1.01ns    31.27mV    -260.6uV   225.7mV
1.49ns    133.6mV    12.05mV    488mV
1.99ns    258.4mV    40.2mV     649.3mV
2.74ns    399.5mV    98.18mV    737.1mV
3.58ns    477mV      166.7mV    764.1mV
6.04ns    529.2mV    285.8mV    777mV
9.77ns    536.1mV    325.2mV    777.4mV
50ns      535.9mV    332.2mV    776.2mV
| Removed startup time: 0s 0s 0s  .
| Removed end time: 10.0ns.
[Falling Waveform]
R_fixture   = 50.0
V_fixture   = 0V
V_fixture_min = 0V
V_fixture_max = 0V
0s        535.9mV    332.2mV    776.1mV
184ps     535.5mV    332.2mV    789.9mV
254ps     545.5mV    332.2mV    507.1mV
308ps     400.1mV    336.2mV    313.6mV
366ps     248.9mV    348.1mV    191.5mV
444ps     127.9mV    229.7mV    104.7mV
540ps     62.51mV    110mV      45.96mV
720ps     19.15mV    28.56mV    8.871mV
1.47ns    462.9uV    999.7uV    264.8uV
10ns      1.739uV    11.14uV    986.9nV
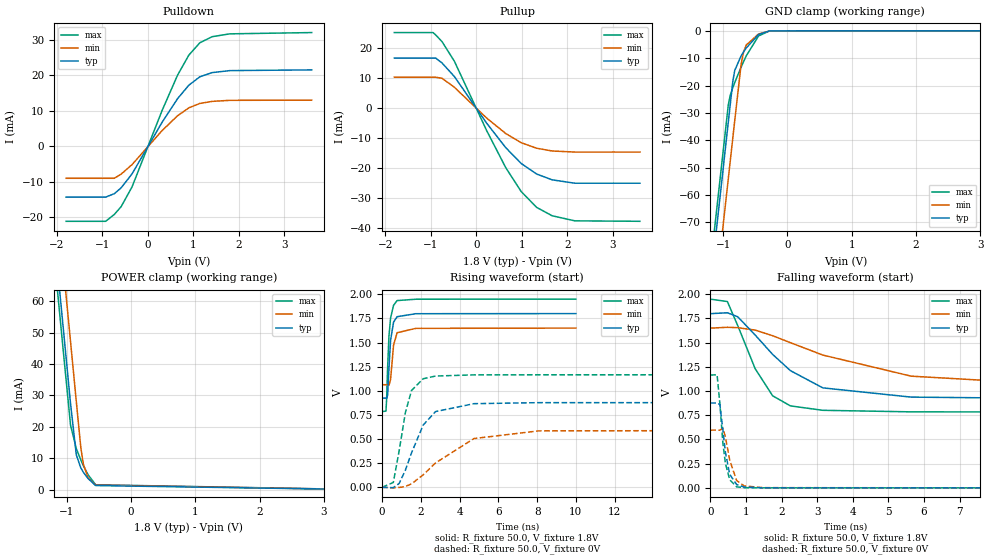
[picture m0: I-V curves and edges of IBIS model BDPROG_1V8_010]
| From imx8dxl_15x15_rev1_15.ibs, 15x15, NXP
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[Model] BDPROG_1V8_010
Model_type I/O
Polarity   Non-Inverting
Enable   Active-Low
| CAP_THRESHOLD on pad IO is "CMOS" :
| Rising=10.0% of vdde1v8   Falling=90.0% of vdde1v8
| C_comp min and max val. don't necessarily correlate with the min and max pvt
| but are the smallest and greatest pad capacitance found.
| var   typ   min   max
C_comp   2.01935pF  1.99430pF  2.04355pF
Vinl = 577.5mV
Vinh = 1.2675V
Vmeas = 900.0mV   | Reference voltage for timing measurements
Cref  = 15.0pF   | Timing specification test load capacitance value
Rref  = 1.0MOhm   | Timing specification test load resistance value
Vref  = 1.8V   | Timing specification test load voltage
[Model Spec]
| TIME_THRESHOLD on pin ZI is "CORE" :
| Rising=50.0% of vdd   Falling=50.0% of vdd
Vinl 630.00000mV 577.50000mV 682.50000mV
Vinh 1.17000V 1.07250V 1.26750V
| variable   typ   min   max
[Temperature Range] 25.0 125.0 -40.0
| variable   typ   min   max
[Voltage Range] 1.8V 1.65V 1.95V
| variable   typ   min   max
[POWER Clamp Reference] 1.8V 1.65V 1.95V
| variable   typ   min   max
[GND Clamp Reference] 0V 0V 0V
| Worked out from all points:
|   slope of the pulldown table from 0 to 0.27 V, typ, clamps not added: 45.8 ohm
|   slope of the pullup table from 0 to 0.27 V, typ, clamps not added: 46.6 ohm
|   GND clamp passes 1 mA (typ) near -0.42 V on its own axis
|   POWER clamp passes 1 mA (typ) near -0.53 V on its own axis
|   rising waveform, R_fixture 50.0, V_fixture 1.8V: 20-80 % time 168ps typ, 179ps min, 163ps max; typ from 0.925 V to 1.8 V
|   falling waveform, R_fixture 50.0, V_fixture 1.8V: 20-80 % time 1.56ns typ, 3.13ns min, 867ps max; typ from 1.8 V to 0.925 V
|   rising waveform, R_fixture 50.0, V_fixture 0V: 20-80 % time 1.11ns typ, 2.29ns min, 621ps max; typ from 0 V to 0.877 V
|   falling waveform, R_fixture 50.0, V_fixture 0V: 20-80 % time 191ps typ, 224ps min, 178ps max; typ from 0.877 V to 0 V
[POWER Clamp]
-1.8V     210.1mA    229.8mA    202.8mA
-1.21V    84.68mA    104.4mA    77.47mA
-1.18V    78.31mA    98.07mA    71.09mA
-1.15V    71.93mA    91.7mA     64.72mA
-1.06V    52.81mA    72.57mA    45.59mA
-940mV    27.31mA    47.07mA    20.48mA
-850mV    11.02mA    27.95mA    13.03mA
-780mV    6.883mA    13.28mA    9.41mA
-740mV    5.505mA    8.047mA    7.575mA
-670mV    3.576mA    3.902mA    4.805mA
-550mV    1.291mA    1.449mA    1.548mA
3.6V      0A         0A         0A
[GND Clamp]
-1.8V     -220.4mA   -241.1mA   -213.8mA
-920mV    -33.4mA    -54.08mA   -27.05mA
-890mV    -27.02mA   -47.71mA   -23.58mA
-850mV    -18.55mA   -39.21mA   -20.74mA
-820mV    -14.49mA   -32.83mA   -18.91mA
-720mV    -9.101mA   -12.08mA   -13.24mA
-680mV    -7.624mA   -7.509mA   -11.13mA
-640mV    -6.25mA    -5.182mA   -9.119mA
-450mV    -1.363mA   -1.162mA   -1.887mA
-280mV    -38.48uA   -82.86uA   -27.73uA
3.6V      43.32nA    1.229uA    123.6nA
| variable   typ   min   max
[Pullup Reference] 1.8V 1.65V 1.95V
| variable   typ   min   max
[Pulldown Reference] 0V 0V 0V
[Pullup]
-1.8V     16.78mA    10.39mA    25.32mA
-950mV    16.78mA    10.39mA    25.32mA
-890mV    16.78mA    10.39mA    24.52mA
-750mV    15.14mA    10.03mA    22.26mA
-480mV    10.63mA    7.04mA     15.74mA
230mV     -4.962mA   -3.254mA   -7.443mA
650mV     -13.16mA   -8.426mA   -19.84mA
990mV     -18.44mA   -11.5mA    -27.83mA
1.33V     -21.97mA   -13.34mA   -33.12mA
1.67V     -23.9mA    -14.26mA   -35.91mA
2.17V     -25.03mA   -14.62mA   -37.61mA
3.6V      -25.03mA   -14.62mA   -37.76mA
[Pulldown]
-1.8V     -14.3mA    -9mA       -21.1mA
-930mV    -14.3mA    -9mA       -21.1mA
-740mV    -13.33mA   -9mA       -19.17mA
-590mV    -11.69mA   -7.828mA   -16.98mA
-350mV    -7.758mA   -5.153mA   -11.42mA
310mV     6.742mA    4.406mA    10.05mA
650mV     13.38mA    8.585mA    19.99mA
900mV     17.2mA     10.82mA    25.67mA
1.14V     19.54mA    12.05mA    29.11mA
1.41V     20.73mA    12.63mA    30.83mA
1.8V      21.29mA    12.93mA    31.63mA
3.6V      21.49mA    12.98mA    31.99mA
[Ramp]
dV/dt_r 526.09047mV/1.10841ns 357.98866mV/2.2901ns 699.58751mV/620.66038ps
dV/dt_f 525.25392mV/1.56411ns 352.46609mV/3.13186ns 698.91873mV/866.86933ps
R_load = 50.0
| Removed startup time: 0s 0s 0s  .
| Removed end time: 10.0ns.
[Rising Waveform]
R_fixture   = 50.0
V_fixture   = 1.8V
V_fixture_min = 1.65V
V_fixture_max = 1.95V
0s        924.6mV    1.063V     785.2mV
202ps     924.7mV    1.063V     789.3mV
236ps     921.8mV    1.063V     915.1mV
286ps     952.9mV    1.063V     1.234V
354ps     1.224V     1.056V     1.561V
438ps     1.522V     1.114V     1.753V
594ps     1.711V     1.473V     1.886V
776ps     1.768V     1.602V     1.935V
1.742ns   1.799V     1.647V     1.949V
10ns      1.8V       1.65V      1.95V
| Removed startup time: 0s 0s 0s  .
| Removed end time: 50.0ns.
[Falling Waveform]
R_fixture   = 50.0
V_fixture   = 1.8V
V_fixture_min = 1.65V
V_fixture_max = 1.95V
0s        1.8V       1.65V      1.95V
480ps     1.809V     1.659V     1.925V
770ps     1.768V     1.655V     1.677V
1.26ns    1.579V     1.63V      1.231V
1.75ns    1.379V     1.572V     951.3mV
2.25ns    1.211V     1.5V       846.9mV
3.16ns    1.033V     1.372V     801.3mV
5.64ns    937.6mV    1.154V     785.3mV
9.17ns    925.2mV    1.08V      784.2mV
50ns      924.6mV    1.063V     785.1mV
| Removed startup time: 0s 0s 0s  .
| Removed end time: 50.0ns.
[Rising Waveform]
R_fixture   = 50.0
V_fixture   = 0V
V_fixture_min = 0V
V_fixture_max = 0V
0s        248.6nV    1.03uV     472.9nV
580ps     -3.865mV   -5.795mV   49.74mV
880ps     38.97mV    -1.638mV   375.2mV
1.2ns     175.9mV    7.799mV    771.9mV
1.52ns    356.3mV    35.73mV    1.003V
2.12ns    644.9mV    129.3mV    1.125V
2.76ns    784.7mV    252.4mV    1.153V
4.74ns    866.6mV    505.2mV    1.165V
8.08ns    877.1mV    584.7mV    1.166V
50ns      876.8mV    596.6mV    1.165V
| Removed startup time: 0s 0s 0s  .
| Removed end time: 10.0ns.
[Falling Waveform]
R_fixture   = 50.0
V_fixture   = 0V
V_fixture_min = 0V
V_fixture_max = 0V
0s        876.8mV    596.6mV    1.165V
190ps     876.2mV    596.6mV    1.169V
268ps     861.4mV    596.4mV    874.5mV
354ps     599.9mV    614.3mV    460.4mV
424ps     368.5mV    527mV      254.9mV
546ps     138.6mV    285.2mV    83.16mV
740ps     34.86mV    75.3mV     10.49mV
948ps     7.898mV    20.62mV    1.891mV
1.472ns   687.7uV    2.042mV    338uV
10ns      1.565uV    12.28uV    663.5nV
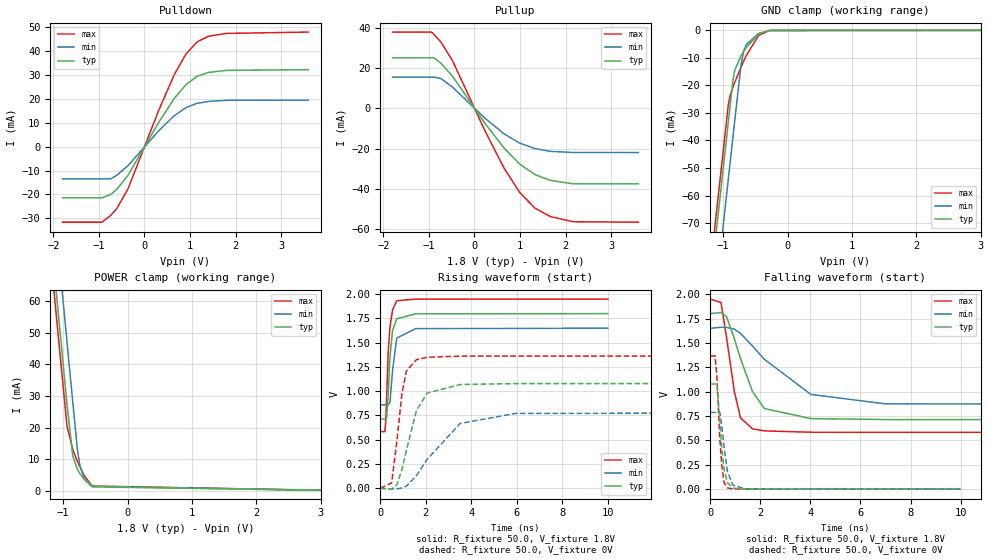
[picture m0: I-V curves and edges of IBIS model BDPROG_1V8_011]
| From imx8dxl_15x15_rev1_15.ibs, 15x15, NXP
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[Model] BDPROG_1V8_011
Model_type I/O
Polarity   Non-Inverting
Enable   Active-Low
| CAP_THRESHOLD on pad IO is "CMOS" :
| Rising=10.0% of vdde1v8   Falling=90.0% of vdde1v8
| C_comp min and max val. don't necessarily correlate with the min and max pvt
| but are the smallest and greatest pad capacitance found.
| var   typ   min   max
C_comp   2.01865pF  1.99345pF  2.04300pF
Vinl = 577.5mV
Vinh = 1.2675V
Vmeas = 900.0mV   | Reference voltage for timing measurements
Cref  = 15.0pF   | Timing specification test load capacitance value
Rref  = 1.0MOhm   | Timing specification test load resistance value
Vref  = 1.8V   | Timing specification test load voltage
[Model Spec]
| TIME_THRESHOLD on pin ZI is "CORE" :
| Rising=50.0% of vdd   Falling=50.0% of vdd
Vinl 630.00000mV 577.50000mV 682.50000mV
Vinh 1.17000V 1.07250V 1.26750V
| variable   typ   min   max
[Temperature Range] 25.0 125.0 -40.0
| variable   typ   min   max
[Voltage Range] 1.8V 1.65V 1.95V
| variable   typ   min   max
[POWER Clamp Reference] 1.8V 1.65V 1.95V
| variable   typ   min   max
[GND Clamp Reference] 0V 0V 0V
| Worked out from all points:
|   slope of the pulldown table from 0 to 0.27 V, typ, clamps not added: 30.5 ohm
|   slope of the pullup table from 0 to 0.27 V, typ, clamps not added: 31.1 ohm
|   GND clamp passes 1 mA (typ) near -0.42 V on its own axis
|   POWER clamp passes 1 mA (typ) near -0.53 V on its own axis
|   rising waveform, R_fixture 50.0, V_fixture 1.8V: 20-80 % time 168ps typ, 185ps min, 163ps max; typ from 0.714 V to 1.8 V
|   falling waveform, R_fixture 50.0, V_fixture 1.8V: 20-80 % time 915ps typ, 2ns min, 484ps max; typ from 1.8 V to 0.714 V
|   rising waveform, R_fixture 50.0, V_fixture 0V: 20-80 % time 721ps typ, 1.56ns min, 392ps max; typ from 0 V to 1.08 V
|   falling waveform, R_fixture 50.0, V_fixture 0V: 20-80 % time 196ps typ, 236ps min, 172ps max; typ from 1.08 V to 0 V
[POWER Clamp]
-1.8V     210.1mA    229.8mA    202.8mA
-1.21V    84.68mA    104.4mA    77.47mA
-1.18V    78.31mA    98.07mA    71.09mA
-1.15V    71.93mA    91.7mA     64.72mA
-1.06V    52.81mA    72.57mA    45.59mA
-940mV    27.31mA    47.07mA    20.48mA
-850mV    11.02mA    27.95mA    13.03mA
-780mV    6.883mA    13.28mA    9.41mA
-740mV    5.505mA    8.047mA    7.575mA
-670mV    3.576mA    3.902mA    4.805mA
-550mV    1.291mA    1.449mA    1.548mA
3.6V      0A         0A         0A
[GND Clamp]
-1.8V     -220.4mA   -241.1mA   -213.8mA
-920mV    -33.4mA    -54.08mA   -27.05mA
-890mV    -27.02mA   -47.71mA   -23.58mA
-850mV    -18.55mA   -39.21mA   -20.74mA
-820mV    -14.49mA   -32.83mA   -18.91mA
-720mV    -9.101mA   -12.08mA   -13.24mA
-680mV    -7.624mA   -7.509mA   -11.13mA
-640mV    -6.25mA    -5.182mA   -9.119mA
-450mV    -1.363mA   -1.162mA   -1.887mA
-280mV    -38.48uA   -82.86uA   -27.73uA
3.6V      43.32nA    1.229uA    123.6nA
| variable   typ   min   max
[Pullup Reference] 1.8V 1.65V 1.95V
| variable   typ   min   max
[Pulldown Reference] 0V 0V 0V
[Pullup]
-1.8V     25.17mA    15.58mA    37.98mA
-950mV    25.17mA    15.58mA    37.98mA
-890mV    25.17mA    15.58mA    36.78mA
-740mV    22.52mA    14.91mA    33.11mA
-480mV    15.94mA    10.56mA    23.62mA
230mV     -7.444mA   -4.881mA   -11.16mA
650mV     -19.74mA   -12.64mA   -29.76mA
990mV     -27.66mA   -17.25mA   -41.74mA
1.33V     -32.96mA   -20.01mA   -49.67mA
1.67V     -35.85mA   -21.39mA   -53.87mA
2.17V     -37.54mA   -21.94mA   -56.42mA
3.6V      -37.54mA   -21.94mA   -56.64mA
[Pulldown]
-1.8V     -21.45mA   -13.5mA    -31.66mA
-930mV    -21.45mA   -13.5mA    -31.66mA
-740mV    -20mA      -13.5mA    -28.76mA
-610mV    -17.91mA   -12.01mA   -25.99mA
-360mV    -11.95mA   -7.936mA   -17.58mA
310mV     10.12mA    6.614mA    15.09mA
650mV     20.08mA    12.89mA    29.99mA
910mV     26mA       16.35mA    38.8mA
1.16V     29.52mA    18.19mA    43.97mA
1.41V     31.11mA    18.96mA    46.27mA
1.8V      31.96mA    19.42mA    47.46mA
3.6V      32.26mA    19.49mA    48.01mA
[Ramp]
dV/dt_r 647.50715mV/720.58422ps 472.30559mV/1.56445ns 817.54226mV/391.74939ps
dV/dt_f 651.6126mV/914.71562ps 474.15489mV/2.00253ns 819.77798mV/483.64504ps
R_load = 50.0
| Removed startup time: 0s 0s 0s  .
| Removed end time: 10.0ns.
[Rising Waveform]
R_fixture   = 50.0
V_fixture   = 1.8V
V_fixture_min = 1.65V
V_fixture_max = 1.95V
0s        714mV      859.8mV    583.8mV
202ps     714mV      859.8mV    583.9mV
242ps     711.3mV    859.8mV    696.2mV
276ps     717.2mV    859.7mV    912.6mV
346ps     950.4mV    857.7mV    1.392V
426ps     1.357V     884.1mV    1.664V
540ps     1.627V     1.217V     1.837V
724ps     1.747V     1.548V     1.933V
1.546ns   1.798V     1.645V     1.949V
10ns      1.8V       1.65V      1.95V
| Removed startup time: 0s 0s 0s  .
| Removed end time: 50.0ns.
[Falling Waveform]
R_fixture   = 50.0
V_fixture   = 1.8V
V_fixture_min = 1.65V
V_fixture_max = 1.95V
0s        1.8V       1.65V      1.95V
430ps     1.813V     1.661V     1.915V
650ps     1.769V     1.659V     1.556V
960ps     1.545V     1.642V     1.004V
1.21ns    1.337V     1.597V     730.2mV
1.69ns    1V         1.468V     618.8mV
2.16ns    827mV      1.332V     597.7mV
4.02ns    723.9mV    971.9mV    584.1mV
6.99ns    714.2mV    875.1mV    583.1mV
50ns      714mV      859.7mV    583.7mV
| Removed startup time: 0s 0s 0s  .
| Removed end time: 50.0ns.
[Rising Waveform]
R_fixture   = 50.0
V_fixture   = 0V
V_fixture_min = 0V
V_fixture_max = 0V
0s        194.8nV    787.9nV    356.7nV
500ps     -9.232mV   -7.039mV   54.51mV
730ps     37.14mV    -5.512mV   487.8mV
950ps     191.8mV    2.256mV    973.4mV
1.15ns    393.5mV    23.06mV    1.209V
1.59ns    801.6mV    130.7mV    1.326V
2.06ns    980.8mV    298.1mV    1.35V
3.51ns    1.069V     667.9mV    1.362V
5.94ns    1.079V     771.3mV    1.363V
50ns      1.079V     787.2mV    1.362V
| Removed startup time: 0s 0s 0s  .
| Removed end time: 10.0ns.
[Falling Waveform]
R_fixture   = 50.0
V_fixture   = 0V
V_fixture_min = 0V
V_fixture_max = 0V
0s        1.079V     787.1mV    1.362V
190ps     1.079V     787.1mV    1.368V
262ps     1.079V     787.1mV    1.165V
376ps     744.6mV    792.9mV    535.8mV
454ps     437.3mV    665.8mV    259.5mV
550ps     202.7mV    436.2mV    70.1mV
682ps     69.01mV    186.9mV    12.4mV
892ps     10.85mV    44.44mV    2.073mV
1.35ns    1.042mV    4.166mV    413uV
10ns      566.1nV    6.041uV    447.7nV
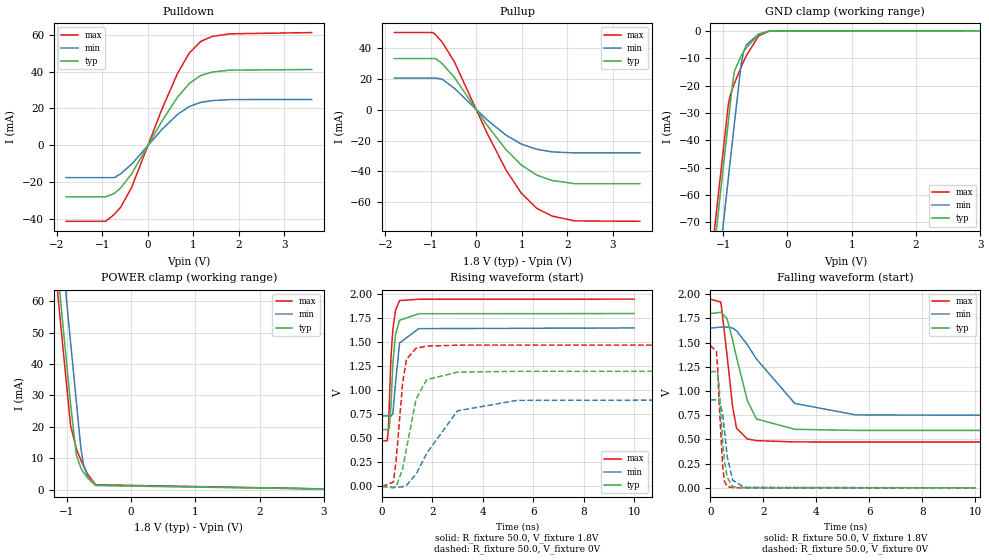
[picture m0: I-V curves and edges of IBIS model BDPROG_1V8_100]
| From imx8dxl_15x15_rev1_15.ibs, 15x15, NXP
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[Model] BDPROG_1V8_100
Model_type I/O
Polarity   Non-Inverting
Enable   Active-Low
| CAP_THRESHOLD on pad IO is "CMOS" :
| Rising=10.0% of vdde1v8   Falling=90.0% of vdde1v8
| C_comp min and max val. don't necessarily correlate with the min and max pvt
| but are the smallest and greatest pad capacitance found.
| var   typ   min   max
C_comp   2.01815pF  1.99285pF  2.04260pF
Vinl = 577.5mV
Vinh = 1.2675V
Vmeas = 900.0mV   | Reference voltage for timing measurements
Cref  = 15.0pF   | Timing specification test load capacitance value
Rref  = 1.0MOhm   | Timing specification test load resistance value
Vref  = 1.8V   | Timing specification test load voltage
[Model Spec]
| TIME_THRESHOLD on pin ZI is "CORE" :
| Rising=50.0% of vdd   Falling=50.0% of vdd
Vinl 630.00000mV 577.50000mV 682.50000mV
Vinh 1.17000V 1.07250V 1.26750V
| variable   typ   min   max
[Temperature Range] 25.0 125.0 -40.0
| variable   typ   min   max
[Voltage Range] 1.8V 1.65V 1.95V
| variable   typ   min   max
[POWER Clamp Reference] 1.8V 1.65V 1.95V
| variable   typ   min   max
[GND Clamp Reference] 0V 0V 0V
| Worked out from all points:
|   slope of the pulldown table from 0 to 0.27 V, typ, clamps not added: 23.3 ohm
|   slope of the pullup table from 0 to 0.27 V, typ, clamps not added: 23.8 ohm
|   GND clamp passes 1 mA (typ) near -0.42 V on its own axis
|   POWER clamp passes 1 mA (typ) near -0.53 V on its own axis
|   rising waveform, R_fixture 50.0, V_fixture 1.8V: 20-80 % time 168ps typ, 185ps min, 161ps max; typ from 0.593 V to 1.8 V
|   falling waveform, R_fixture 50.0, V_fixture 1.8V: 20-80 % time 670ps typ, 1.52ns min, 349ps max; typ from 1.8 V to 0.593 V
|   rising waveform, R_fixture 50.0, V_fixture 0V: 20-80 % time 548ps typ, 1.21ns min, 295ps max; typ from 0 V to 1.2 V
|   falling waveform, R_fixture 50.0, V_fixture 0V: 20-80 % time 195ps typ, 242ps min, 159ps max; typ from 1.2 V to 0 V
[POWER Clamp]
-1.8V     210.1mA    229.8mA    202.8mA
-1.21V    84.68mA    104.4mA    77.47mA
-1.18V    78.31mA    98.07mA    71.09mA
-1.15V    71.93mA    91.7mA     64.72mA
-1.06V    52.81mA    72.57mA    45.59mA
-940mV    27.31mA    47.07mA    20.48mA
-850mV    11.02mA    27.95mA    13.03mA
-780mV    6.883mA    13.28mA    9.41mA
-740mV    5.505mA    8.047mA    7.575mA
-670mV    3.576mA    3.902mA    4.805mA
-550mV    1.291mA    1.449mA    1.548mA
3.6V      0A         0A         0A
[GND Clamp]
-1.8V     -220.4mA   -241.1mA   -213.8mA
-920mV    -33.4mA    -54.08mA   -27.05mA
-890mV    -27.02mA   -47.71mA   -23.58mA
-850mV    -18.55mA   -39.21mA   -20.74mA
-820mV    -14.49mA   -32.83mA   -18.91mA
-720mV    -9.101mA   -12.08mA   -13.24mA
-680mV    -7.624mA   -7.509mA   -11.13mA
-640mV    -6.25mA    -5.182mA   -9.119mA
-450mV    -1.363mA   -1.162mA   -1.887mA
-280mV    -38.48uA   -82.86uA   -27.73uA
3.6V      43.32nA    1.229uA    123.6nA
| variable   typ   min   max
[Pullup Reference] 1.8V 1.65V 1.95V
| variable   typ   min   max
[Pulldown Reference] 0V 0V 0V
[Pullup]
-1.8V     33.07mA    20.43mA    49.86mA
-950mV    33.07mA    20.43mA    49.86mA
-890mV    33.07mA    20.43mA    48.28mA
-750mV    29.82mA    19.73mA    43.81mA
-480mV    20.88mA    13.81mA    30.94mA
230mV     -9.721mA   -6.353mA   -14.6mA
650mV     -25.66mA   -16.37mA   -38.73mA
990mV     -35.74mA   -22.2mA    -53.97mA
1.33V     -42.32mA   -25.62mA   -63.78mA
1.67V     -45.84mA   -27.32mA   -68.86mA
2.17V     -47.89mA   -27.98mA   -71.95mA
3.6V      -47.89mA   -27.98mA   -72.21mA
[Pulldown]
-1.8V     -28.11mA   -17.65mA   -41.41mA
-930mV    -28.11mA   -17.65mA   -41.41mA
-740mV    -26.23mA   -17.65mA   -37.66mA
-600mV    -23.25mA   -15.56mA   -33.73mA
-360mV    -15.66mA   -10.38mA   -23.03mA
310mV     13.23mA    8.618mA    19.74mA
650mV     26.12mA    16.7mA     39.05mA
910mV     33.6mA     21.05mA    50.15mA
1.16V     37.88mA    23.29mA    56.42mA
1.41V     39.77mA    24.23mA    59.15mA
1.8V      40.79mA    24.79mA    60.58mA
3.6V      41.16mA    24.87mA    61.25mA
[Ramp]
dV/dt_r 719.33273mV/547.7354ps 545.21675mV/1.21284ns 883.44257mV/295.29286ps
dV/dt_f 724.40221mV/669.71551ps 549.78164mV/1.51541ns 885.73475mV/348.94662ps
R_load = 50.0
| Removed startup time: 0s 0s 0s  .
| Removed end time: 10.0ns.
[Rising Waveform]
R_fixture   = 50.0
V_fixture   = 1.8V
V_fixture_min = 1.65V
V_fixture_max = 1.95V
0s        592.7mV    733.7mV    473.8mV
206ps     592.7mV    733.7mV    475.6mV
250ps     588.9mV    733.7mV    591.5mV
286ps     607.1mV    733.7mV    844.9mV
352ps     834.8mV    731.1mV    1.339V
428ps     1.277V     757.4mV    1.629V
532ps     1.58V      1.074V     1.834V
696ps     1.73V      1.494V     1.935V
1.454ns   1.798V     1.643V     1.949V
10ns      1.8V       1.65V      1.95V
| Removed startup time: 0s 0s 0s  .
| Removed end time: 50.0ns.
[Falling Waveform]
R_fixture   = 50.0
V_fixture   = 1.8V
V_fixture_min = 1.65V
V_fixture_max = 1.95V
0s        1.8V       1.65V      1.95V
400ps     1.814V     1.661V     1.919V
630ps     1.75V      1.661V     1.376V
840ps     1.531V     1.651V     841.2mV
990ps     1.348V     1.623V     616mV
1.4ns     901.1mV    1.478V     505.4mV
1.74ns    712mV      1.332V     487.8mV
3.19ns    604.9mV    872.2mV    474.6mV
5.5ns     593.5mV    753.5mV    473.4mV
50ns      592.7mV    733.7mV    473.8mV
| Removed startup time: 0s 0s 0s  .
| Removed end time: 50.0ns.
[Rising Waveform]
R_fixture   = 50.0
V_fixture   = 0V
V_fixture_min = 0V
V_fixture_max = 0V
0s        162nV      641.2nV    289.9nV
450ps     -14.25mV   -7.285mV   45.65mV
560ps     -2.468mV   -8.99mV    278.7mV
820ps     186.5mV    -2.983mV   1.088V
970ps     396.3mV    12.31mV    1.324V
1.35ns    910.2mV    128.3mV    1.439V
1.77ns    1.112V     344.1mV    1.461V
2.99ns    1.19V      787.2mV    1.471V
5.36ns    1.199V     896.5mV    1.472V
50ns      1.199V     908.7mV    1.471V
| Removed startup time: 0s 0s 0s  .
| Removed end time: 10.0ns.
[Falling Waveform]
R_fixture   = 50.0
V_fixture   = 0V
V_fixture_min = 0V
V_fixture_max = 0V
0s        1.199V     908.7mV    1.471V
228ps     1.203V     908.7mV    1.411V
274ps     1.184V     908.4mV    1.252V
330ps     1.058V     915.3mV    903.8mV
466ps     480mV      767.2mV    226.9mV
534ps     278.4mV    587.5mV    66.26mV
640ps     109.4mV    320.1mV    13.7mV
846ps     12.85mV    79.06mV    2.3mV
1.274ns   1.227mV    6.102mV    452.5uV
10ns      364.4nV    4.087uV    356.3nV
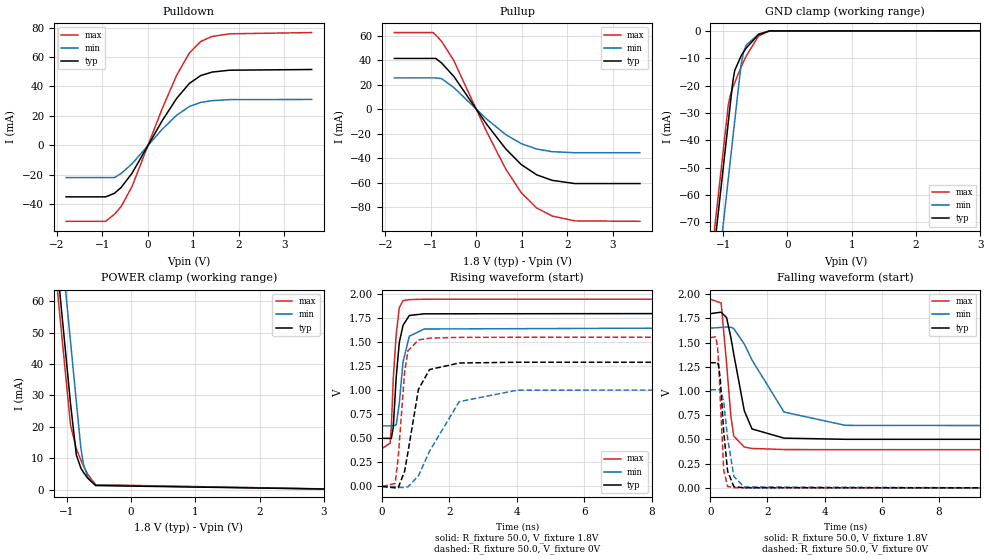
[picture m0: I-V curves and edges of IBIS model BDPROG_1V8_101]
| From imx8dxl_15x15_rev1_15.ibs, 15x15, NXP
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[Model] BDPROG_1V8_101
Model_type I/O
Polarity   Non-Inverting
Enable   Active-Low
| CAP_THRESHOLD on pad IO is "CMOS" :
| Rising=10.0% of vdde1v8   Falling=90.0% of vdde1v8
| C_comp min and max val. don't necessarily correlate with the min and max pvt
| but are the smallest and greatest pad capacitance found.
| var   typ   min   max
C_comp   2.01730pF  1.99185pF  2.04200pF
Vinl = 577.5mV
Vinh = 1.2675V
Vmeas = 900.0mV   | Reference voltage for timing measurements
Cref  = 15.0pF   | Timing specification test load capacitance value
Rref  = 1.0MOhm   | Timing specification test load resistance value
Vref  = 1.8V   | Timing specification test load voltage
[Model Spec]
| TIME_THRESHOLD on pin ZI is "CORE" :
| Rising=50.0% of vdd   Falling=50.0% of vdd
Vinl 630.00000mV 577.50000mV 682.50000mV
Vinh 1.17000V 1.07250V 1.26750V
| variable   typ   min   max
[Temperature Range] 25.0 125.0 -40.0
| variable   typ   min   max
[Voltage Range] 1.8V 1.65V 1.95V
| variable   typ   min   max
[POWER Clamp Reference] 1.8V 1.65V 1.95V
| variable   typ   min   max
[GND Clamp Reference] 0V 0V 0V
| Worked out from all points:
|   slope of the pulldown table from 0 to 0.27 V, typ, clamps not added: 18.7 ohm
|   slope of the pullup table from 0 to 0.27 V, typ, clamps not added: 18.9 ohm
|   GND clamp passes 1 mA (typ) near -0.42 V on its own axis
|   POWER clamp passes 1 mA (typ) near -0.53 V on its own axis
|   rising waveform, R_fixture 50.0, V_fixture 1.8V: 20-80 % time 168ps typ, 187ps min, 149ps max; typ from 0.501 V to 1.8 V
|   falling waveform, R_fixture 50.0, V_fixture 1.8V: 20-80 % time 494ps typ, 1.14ns min, 257ps max; typ from 1.8 V to 0.501 V
|   rising waveform, R_fixture 50.0, V_fixture 0V: 20-80 % time 376ps typ, 841ps min, 203ps max; typ from 0 V to 1.29 V
|   falling waveform, R_fixture 50.0, V_fixture 0V: 20-80 % time 192ps typ, 249ps min, 140ps max; typ from 1.29 V to 0 V
[POWER Clamp]
-1.8V     210.1mA    229.8mA    202.8mA
-1.21V    84.68mA    104.4mA    77.47mA
-1.18V    78.31mA    98.07mA    71.09mA
-1.15V    71.93mA    91.7mA     64.72mA
-1.06V    52.81mA    72.57mA    45.59mA
-940mV    27.31mA    47.07mA    20.48mA
-850mV    11.02mA    27.95mA    13.03mA
-780mV    6.883mA    13.28mA    9.41mA
-740mV    5.505mA    8.047mA    7.575mA
-670mV    3.576mA    3.902mA    4.805mA
-550mV    1.291mA    1.449mA    1.548mA
3.6V      0A         0A         0A
[GND Clamp]
-1.8V     -220.4mA   -241.1mA   -213.8mA
-920mV    -33.4mA    -54.08mA   -27.05mA
-890mV    -27.02mA   -47.71mA   -23.58mA
-850mV    -18.55mA   -39.21mA   -20.74mA
-820mV    -14.49mA   -32.83mA   -18.91mA
-720mV    -9.101mA   -12.08mA   -13.24mA
-680mV    -7.624mA   -7.509mA   -11.13mA
-640mV    -6.25mA    -5.182mA   -9.119mA
-450mV    -1.363mA   -1.162mA   -1.887mA
-280mV    -38.48uA   -82.86uA   -27.73uA
3.6V      43.32nA    1.229uA    123.6nA
| variable   typ   min   max
[Pullup Reference] 1.8V 1.65V 1.95V
| variable   typ   min   max
[Pulldown Reference] 0V 0V 0V
[Pullup]
-1.8V     41.51mA    25.65mA    62.6mA
-950mV    41.51mA    25.65mA    62.6mA
-890mV    41.51mA    25.65mA    60.62mA
-760mV    37.76mA    25mA       55.46mA
-490mV    26.73mA    17.68mA    39.6mA
230mV     -12.22mA   -7.994mA   -18.35mA
650mV     -32.3mA    -20.62mA   -48.73mA
990mV     -45.06mA   -28.01mA   -68.03mA
1.33V     -53.44mA   -32.38mA   -80.54mA
1.67V     -57.95mA   -34.55mA   -87.06mA
2.17V     -60.58mA   -35.41mA   -91.03mA
3.6V      -60.58mA   -35.41mA   -91.36mA
[Pulldown]
-1.8V     -35.12mA   -22.03mA   -51.75mA
-930mV    -35.12mA   -22.03mA   -51.75mA
-740mV    -32.77mA   -22.03mA   -47.06mA
-590mV    -28.74mA   -19.22mA   -41.73mA
-350mV    -19.06mA   -12.64mA   -28.04mA
310mV     16.53mA    10.77mA    24.67mA
630mV     31.81mA    20.37mA    47.54mA
910mV     42.02mA    26.33mA    62.72mA
1.16V     47.39mA    29.14mA    70.58mA
1.41V     49.75mA    30.31mA    73.99mA
1.8V      51.03mA    31.01mA    75.78mA
3.6V      51.49mA    31.12mA    76.62mA
[Ramp]
dV/dt_r 776.08167mV/375.92235ps 608.16178mV/841.04106ps 931.73795mV/202.65523ps
dV/dt_f 779.4547mV/493.96327ps 611.70142mV/1.13648ns 933.17547mV/257.31294ps
R_load = 50.0
| Removed startup time: 0s 0s 0s  .
| Removed end time: 10.0ns.
[Rising Waveform]
R_fixture   = 50.0
V_fixture   = 1.8V
V_fixture_min = 1.65V
V_fixture_max = 1.95V
0s        500.9mV    630.5mV    394.7mV
240ps     500.1mV    630.5mV    451mV
274ps     498.8mV    630.5mV    609.5mV
332ps     612.2mV    630.8mV    1.121V
420ps     1.139V     640mV      1.583V
512ps     1.498V     867.3mV    1.861V
622ps     1.677V     1.295V     1.934V
810ps     1.78V      1.564V     1.945V
1.252ns   1.797V     1.639V     1.949V
10ns      1.8V       1.65V      1.95V
| Removed startup time: 0s 0s 0s  .
| Removed end time: 50.0ns.
[Falling Waveform]
R_fixture   = 50.0
V_fixture   = 1.8V
V_fixture_min = 1.65V
V_fixture_max = 1.95V
0s        1.8V       1.65V      1.95V
380ps     1.815V     1.658V     1.909V
570ps     1.759V     1.662V     1.283V
720ps     1.554V     1.659V     742.5mV
820ps     1.384V     1.647V     534.7mV
1.19ns    797mV      1.486V     421.7mV
1.46ns    608.5mV    1.321V     407.2mV
2.58ns    513.8mV    783.5mV    395.7mV
4.73ns    501.6mV    645.7mV    394.5mV
50ns      500.9mV    630.5mV    394.7mV
| Removed startup time: 0s 0s 0s  .
| Removed end time: 50.0ns.
[Rising Waveform]
R_fixture   = 50.0
V_fixture   = 0V
V_fixture_min = 0V
V_fixture_max = 0V
0s        137nV      512.9nV    240.6nV
390ps     -14.66mV   -1.39mV    30.94mV
480ps     -13.56mV   -8.222mV   304.2mV
670ps     159.3mV    -12.03mV   1.195V
770ps     359.2mV    -3.489mV   1.413V
1.08ns    1.01V      110.5mV    1.525V
1.41ns    1.217V     367.9mV    1.544V
2.29ns    1.285V     882.7mV    1.552V
4.01ns    1.293V     1.002V     1.553V
50ns      1.293V     1.014V     1.553V
| Removed startup time: 0s 0s 0s  .
| Removed end time: 10.0ns.
[Falling Waveform]
R_fixture   = 50.0
V_fixture   = 0V
V_fixture_min = 0V
V_fixture_max = 0V
0s        1.293V     1.014V     1.553V
192ps     1.293V     1.014V     1.56V
252ps     1.301V     1.014V     1.458V
296ps     1.25V      1.013V     1.281V
350ps     1.123V     1.023V     905.8mV
470ps     578.4mV    884.1mV    183.5mV
606ps     172.1mV    511.4mV    14.57mV
826ps     12.27mV    118mV      2.256mV
1.182ns   1.628mV    9.412mV    514uV
10ns      253.8nV    1.928uV    293.9nV
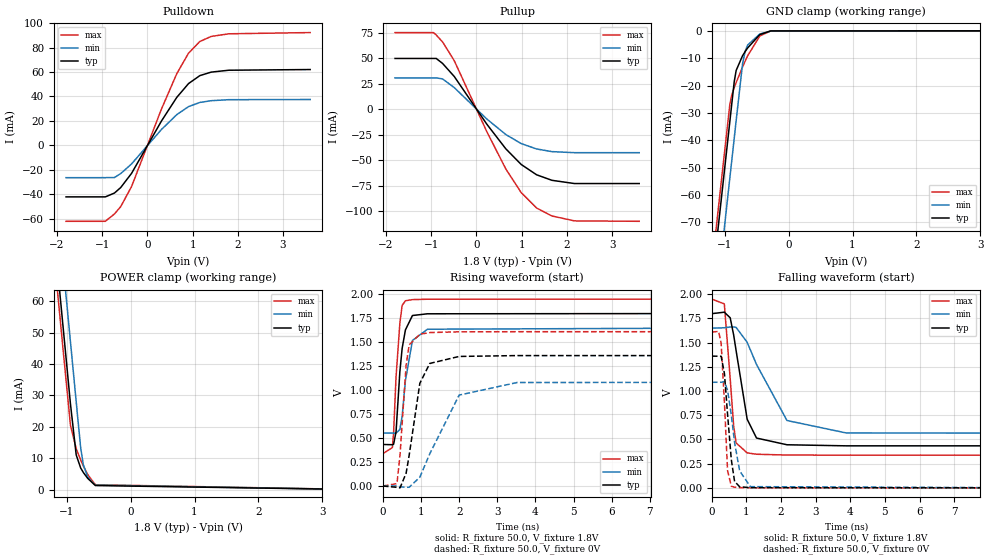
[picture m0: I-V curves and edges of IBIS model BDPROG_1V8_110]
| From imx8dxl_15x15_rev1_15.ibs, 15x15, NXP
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[Model] BDPROG_1V8_110
Model_type I/O
Polarity   Non-Inverting
Enable   Active-Low
| CAP_THRESHOLD on pad IO is "CMOS" :
| Rising=10.0% of vdde1v8   Falling=90.0% of vdde1v8
| C_comp min and max val. don't necessarily correlate with the min and max pvt
| but are the smallest and greatest pad capacitance found.
| var   typ   min   max
C_comp   2.01645pF  1.99075pF  2.04130pF
Vinl = 577.5mV
Vinh = 1.2675V
Vmeas = 900.0mV   | Reference voltage for timing measurements
Cref  = 15.0pF   | Timing specification test load capacitance value
Rref  = 1.0MOhm   | Timing specification test load resistance value
Vref  = 1.8V   | Timing specification test load voltage
[Model Spec]
| TIME_THRESHOLD on pin ZI is "CORE" :
| Rising=50.0% of vdd   Falling=50.0% of vdd
Vinl 630.00000mV 577.50000mV 682.50000mV
Vinh 1.17000V 1.07250V 1.26750V
| variable   typ   min   max
[Temperature Range] 25.0 125.0 -40.0
| variable   typ   min   max
[Voltage Range] 1.8V 1.65V 1.95V
| variable   typ   min   max
[POWER Clamp Reference] 1.8V 1.65V 1.95V
| variable   typ   min   max
[GND Clamp Reference] 0V 0V 0V
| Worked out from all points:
|   slope of the pulldown table from 0 to 0.27 V, typ, clamps not added: 15.5 ohm
|   slope of the pullup table from 0 to 0.27 V, typ, clamps not added: 15.8 ohm
|   GND clamp passes 1 mA (typ) near -0.42 V on its own axis
|   POWER clamp passes 1 mA (typ) near -0.53 V on its own axis
|   rising waveform, R_fixture 50.0, V_fixture 1.8V: 20-80 % time 167ps typ, 189ps min, 137ps max; typ from 0.433 V to 1.8 V
|   falling waveform, R_fixture 50.0, V_fixture 1.8V: 20-80 % time 368ps typ, 854ps min, 192ps max; typ from 1.8 V to 0.433 V
|   rising waveform, R_fixture 50.0, V_fixture 0V: 20-80 % time 309ps typ, 693ps min, 166ps max; typ from 0 V to 1.36 V
|   falling waveform, R_fixture 50.0, V_fixture 0V: 20-80 % time 180ps typ, 255ps min, 118ps max; typ from 1.36 V to 0 V
[POWER Clamp]
-1.8V     210.1mA    229.8mA    202.8mA
-1.21V    84.68mA    104.4mA    77.47mA
-1.18V    78.31mA    98.07mA    71.09mA
-1.15V    71.93mA    91.7mA     64.72mA
-1.06V    52.81mA    72.57mA    45.59mA
-940mV    27.31mA    47.07mA    20.48mA
-850mV    11.02mA    27.95mA    13.03mA
-780mV    6.883mA    13.28mA    9.41mA
-740mV    5.505mA    8.047mA    7.575mA
-670mV    3.576mA    3.902mA    4.805mA
-550mV    1.291mA    1.449mA    1.548mA
3.6V      0A         0A         0A
[GND Clamp]
-1.8V     -220.4mA   -241.1mA   -213.8mA
-920mV    -33.4mA    -54.08mA   -27.05mA
-890mV    -27.02mA   -47.71mA   -23.58mA
-850mV    -18.55mA   -39.21mA   -20.74mA
-820mV    -14.49mA   -32.83mA   -18.91mA
-720mV    -9.101mA   -12.08mA   -13.24mA
-680mV    -7.624mA   -7.509mA   -11.13mA
-640mV    -6.25mA    -5.182mA   -9.119mA
-450mV    -1.363mA   -1.162mA   -1.887mA
-280mV    -38.48uA   -82.86uA   -27.73uA
3.6V      43.32nA    1.229uA    123.6nA
| variable   typ   min   max
[Pullup Reference] 1.8V 1.65V 1.95V
| variable   typ   min   max
[Pulldown Reference] 0V 0V 0V
[Pullup]
-1.8V     49.78mA    30.74mA    75.14mA
-950mV    49.78mA    30.74mA    75.14mA
-890mV    49.78mA    30.74mA    72.76mA
-750mV    44.93mA    29.74mA    66.02mA
-490mV    32.09mA    21.22mA    47.53mA
230mV     -14.67mA   -9.599mA   -22.02mA
650mV     -38.79mA   -24.77mA   -58.52mA
990mV     -54.12mA   -33.66mA   -81.71mA
1.33V     -64.21mA   -38.91mA   -96.78mA
1.67V     -69.64mA   -41.53mA   -104.6mA
2.17V     -72.81mA   -42.56mA   -109.4mA
3.6V      -72.81mA   -42.56mA   -109.8mA
[Pulldown]
-1.8V     -42.2mA    -26.46mA   -62.2mA
-930mV    -42.2mA    -26.46mA   -62.2mA
-730mV    -39.09mA   -26.36mA   -56.2mA
-590mV    -34.54mA   -23.1mA    -50.14mA
-350mV    -22.91mA   -15.19mA   -33.7mA
310mV     19.87mA    12.95mA    29.65mA
650mV     39.28mA    25.13mA    58.7mA
910mV     50.57mA    31.71mA    75.47mA
1.16V     57.07mA    35.1mA     85mA
1.41V     59.93mA    36.52mA    89.14mA
1.8V      61.48mA    37.37mA    91.3mA
3.6V      62.04mA    37.5mA     92.31mA
[Ramp]
dV/dt_r 816.59335mV/308.84839ps 654.5791mV/693.24176ps 965.78962mV/166.26392ps
dV/dt_f 819.96738mV/367.77251ps 658.73091mV/854.48087ps 967.2128mV/191.57306ps
R_load = 50.0
| Removed startup time: 0s 0s 0s  .
| Removed end time: 10.0ns.
[Rising Waveform]
R_fixture   = 50.0
V_fixture   = 1.8V
V_fixture_min = 1.65V
V_fixture_max = 1.95V
0s        433.4mV    552.1mV    338mV
250ps     431.1mV    552.1mV    401mV
282ps     435.6mV    552.1mV    554.8mV
346ps     565.6mV    551.6mV    1.138V
446ps     1.192V     589.5mV    1.698V
506ps     1.436V     730.5mV    1.884V
592ps     1.629V     1.1V       1.933V
776ps     1.779V     1.519V     1.945V
1.17ns    1.797V     1.636V     1.949V
10ns      1.8V       1.65V      1.95V
| Removed startup time: 0s 0s 0s  .
| Removed end time: 50.0ns.
[Falling Waveform]
R_fixture   = 50.0
V_fixture   = 1.8V
V_fixture_min = 1.65V
V_fixture_max = 1.95V
0s        1.8V       1.65V      1.95V
360ps     1.815V     1.654V     1.901V
530ps     1.757V     1.662V     1.125V
630ps     1.579V     1.662V     639.4mV
700ps     1.419V     1.658V     464.2mV
1.02ns    709.2mV    1.504V     361.4mV
1.29ns    514.7mV    1.275V     347.4mV
2.17ns    445.2mV    695.9mV    338.9mV
3.88ns    434.2mV    567.4mV    337.9mV
50ns      433.4mV    552.1mV    338mV
| Removed startup time: 0s 0s 0s  .
| Removed end time: 50.0ns.
[Rising Waveform]
R_fixture   = 50.0
V_fixture   = 0V
V_fixture_min = 0V
V_fixture_max = 0V
0s        118.2nV    414.5nV    204.9nV
370ps     -13.62mV   644.6uV    25.16mV
450ps     -19.15mV   -7.87mV    323mV
610ps     133.6mV    -13.35mV   1.262V
690ps     320.6mV    -12.55mV   1.473V
970ps     1.072V     91.87mV    1.584V
1.23ns    1.279V     335.9mV    1.601V
2ns       1.352V     948.6mV    1.609V
3.52ns    1.361V     1.08V      1.61V
50ns      1.361V     1.091V     1.61V
| Removed startup time: 0s 0s 0s  .
| Removed end time: 10.0ns.
[Falling Waveform]
R_fixture   = 50.0
V_fixture   = 0V
V_fixture_min = 0V
V_fixture_max = 0V
0s        1.361V     1.091V     1.61V
194ps     1.36V      1.091V     1.616V
268ps     1.36V      1.091V     1.496V
364ps     1.179V     1.099V     874.2mV
454ps     758.1mV    1.007V     177.3mV
562ps     291mV      751.6mV    16.32mV
656ps     67.11mV    470.1mV    7.011mV
802ps     11.58mV    176.3mV    2.217mV
1.112ns   1.94mV     12.62mV    552.2uV
10ns      208.2nV    1.336uV    250.4nV
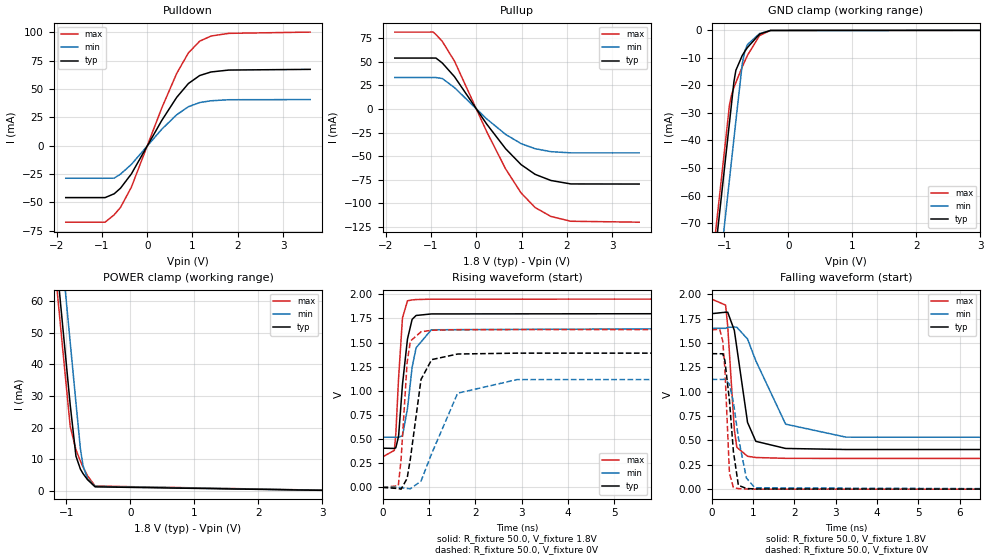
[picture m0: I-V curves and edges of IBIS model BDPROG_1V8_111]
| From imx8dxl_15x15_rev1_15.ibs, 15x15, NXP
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[Model] BDPROG_1V8_111
Model_type I/O
Polarity   Non-Inverting
Enable   Active-Low
| CAP_THRESHOLD on pad IO is "CMOS" :
| Rising=10.0% of vdde1v8   Falling=90.0% of vdde1v8
| C_comp min and max val. don't necessarily correlate with the min and max pvt
| but are the smallest and greatest pad capacitance found.
| var   typ   min   max
C_comp   2.01595pF  1.99020pF  2.04095pF
Vinl = 577.5mV
Vinh = 1.2675V
Vmeas = 900.0mV   | Reference voltage for timing measurements
Cref  = 15.0pF   | Timing specification test load capacitance value
Rref  = 1.0MOhm   | Timing specification test load resistance value
Vref  = 1.8V   | Timing specification test load voltage
[Model Spec]
| TIME_THRESHOLD on pin ZI is "CORE" :
| Rising=50.0% of vdd   Falling=50.0% of vdd
Vinl 630.00000mV 577.50000mV 682.50000mV
Vinh 1.17000V 1.07250V 1.26750V
| variable   typ   min   max
[Temperature Range] 25.0 125.0 -40.0
| variable   typ   min   max
[Voltage Range] 1.8V 1.65V 1.95V
| variable   typ   min   max
[POWER Clamp Reference] 1.8V 1.65V 1.95V
| variable   typ   min   max
[GND Clamp Reference] 0V 0V 0V
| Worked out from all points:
|   slope of the pulldown table from 0 to 0.27 V, typ, clamps not added: 14.3 ohm
|   slope of the pullup table from 0 to 0.27 V, typ, clamps not added: 14.5 ohm
|   GND clamp passes 1 mA (typ) near -0.42 V on its own axis
|   POWER clamp passes 1 mA (typ) near -0.53 V on its own axis
|   rising waveform, R_fixture 50.0, V_fixture 1.8V: 20-80 % time 157ps typ, 189ps min, 113ps max; typ from 0.406 V to 1.8 V
|   falling waveform, R_fixture 50.0, V_fixture 1.8V: 20-80 % time 282ps typ, 655ps min, 147ps max; typ from 1.8 V to 0.406 V
|   rising waveform, R_fixture 50.0, V_fixture 0V: 20-80 % time 233ps typ, 515ps min, 128ps max; typ from 0 V to 1.39 V
|   falling waveform, R_fixture 50.0, V_fixture 0V: 20-80 % time 159ps typ, 248ps min, 98.6ps max; typ from 1.39 V to 0 V
[POWER Clamp]
-1.8V     210.1mA    229.8mA    202.8mA
-1.21V    84.68mA    104.4mA    77.47mA
-1.18V    78.31mA    98.07mA    71.09mA
-1.15V    71.93mA    91.7mA     64.72mA
-1.06V    52.81mA    72.57mA    45.59mA
-940mV    27.31mA    47.07mA    20.48mA
-850mV    11.02mA    27.95mA    13.03mA
-780mV    6.883mA    13.28mA    9.41mA
-740mV    5.505mA    8.047mA    7.575mA
-670mV    3.576mA    3.902mA    4.805mA
-550mV    1.291mA    1.449mA    1.548mA
3.6V      0A         0A         0A
[GND Clamp]
-1.8V     -220.4mA   -241.1mA   -213.8mA
-920mV    -33.4mA    -54.08mA   -27.05mA
-890mV    -27.02mA   -47.71mA   -23.58mA
-850mV    -18.55mA   -39.21mA   -20.74mA
-820mV    -14.49mA   -32.83mA   -18.91mA
-720mV    -9.101mA   -12.08mA   -13.24mA
-680mV    -7.624mA   -7.509mA   -11.13mA
-640mV    -6.25mA    -5.182mA   -9.119mA
-450mV    -1.363mA   -1.162mA   -1.887mA
-280mV    -38.48uA   -82.86uA   -27.73uA
3.6V      43.32nA    1.229uA    123.6nA
| variable   typ   min   max
[Pullup Reference] 1.8V 1.65V 1.95V
| variable   typ   min   max
[Pulldown Reference] 0V 0V 0V
[Pullup]
-1.8V     54.14mA    33.44mA    81.73mA
-950mV    54.14mA    33.44mA    81.73mA
-890mV    54.14mA    33.44mA    79.16mA
-750mV    48.89mA    32.37mA    71.85mA
-480mV    34.28mA    22.69mA    50.78mA
230mV     -15.98mA   -10.46mA   -23.98mA
650mV     -42.29mA   -27.03mA   -63.78mA
990mV     -59.08mA   -36.78mA   -89.18mA
1.3V      -69.45mA   -42.2mA    -104.7mA
1.65V     -75.98mA   -45.36mA   -114.2mA
2.09V     -79.65mA   -46.62mA   -119.3mA
3.6V      -79.76mA   -46.62mA   -120.3mA
[Pulldown]
-1.8V     -45.74mA   -28.68mA   -67.43mA
-930mV    -45.74mA   -28.68mA   -67.43mA
-730mV    -42.38mA   -28.58mA   -60.92mA
-590mV    -37.44mA   -25.04mA   -54.36mA
-350mV    -24.83mA   -16.47mA   -36.53mA
320mV     22.21mA    14.48mA    33.15mA
650mV     42.59mA    27.26mA    63.65mA
910mV     54.86mA    34.4mA     81.86mA
1.16V     61.92mA    38.09mA    92.23mA
1.41V     65.04mA    39.63mA    96.72mA
1.8V      66.72mA    40.55mA    99.08mA
3.6V      67.33mA    40.69mA    100.2mA
[Ramp]
dV/dt_r 834.18002mV/232.7853ps 675.38969mV/515.0925ps 978.18463mV/127.41664ps
dV/dt_f 836.35735mV/281.91634ps 678.07066mV/655.20199ps 980.79167mV/146.41424ps
R_load = 50.0
| Removed startup time: 0s 0s 0s  .
| Removed end time: 10.0ns.
[Rising Waveform]
R_fixture   = 50.0
V_fixture   = 1.8V
V_fixture_min = 1.65V
V_fixture_max = 1.95V
0s        406.1mV    519.9mV    315.4mV
254ps     403.3mV    519.9mV    383.6mV
286ps     410.3mV    519.9mV    551.8mV
346ps     530mV      519.5mV    1.132V
430ps     1.067V     534.9mV    1.755V
538ps     1.537V     816.2mV    1.932V
638ps     1.74V      1.243V     1.941V
724ps     1.78V      1.446V     1.945V
1.052ns   1.796V     1.632V     1.949V
10ns      1.8V       1.65V      1.95V
| Removed startup time: 0s 0s 0s  .
| Removed end time: 50.0ns.
[Falling Waveform]
R_fixture   = 50.0
V_fixture   = 1.8V
V_fixture_min = 1.65V
V_fixture_max = 1.95V
0s        1.8V       1.65V      1.95V
340ps     1.815V     1.65V      1.888V
390ps     1.815V     1.66V      1.672V
550ps     1.629V     1.663V     612.5mV
610ps     1.453V     1.661V     429.3mV
870ps     684.2mV    1.54V      337.5mV
1.07ns    490.7mV    1.317V     324.7mV
1.79ns    417.6mV    666.8mV    316.2mV
3.25ns    406.8mV    533.6mV    315.2mV
50ns      406.1mV    519.9mV    315.3mV
| Removed startup time: 0s 0s 0s  .
| Removed end time: 50.0ns.
[Rising Waveform]
R_fixture   = 50.0
V_fixture   = 0V
V_fixture_min = 0V
V_fixture_max = 0V
0s        110.4nV    370.3nV    190.5nV
340ps     -11.87mV   1.033mV    17.28mV
400ps     -18.34mV   -2.823mV   292.6mV
530ps     92.79mV    -10.89mV   1.293V
600ps     295.5mV    -14.4mV    1.515V
830ps     1.118V     65.71mV    1.611V
1.06ns    1.323V     350.4mV    1.627V
1.62ns    1.381V     975.4mV    1.633V
2.9ns     1.39V      1.116V     1.634V
50ns      1.39V      1.126V     1.634V
| Removed startup time: 0s 0s 0s  .
| Removed end time: 10.0ns.
[Falling Waveform]
R_fixture   = 50.0
V_fixture   = 0V
V_fixture_min = 0V
V_fixture_max = 0V
0s        1.39V      1.126V     1.634V
196ps     1.389V     1.126V     1.64V
270ps     1.389V     1.126V     1.52V
322ps     1.319V     1.127V     1.234V
432ps     910mV      1.077V     164mV
528ps     385.6mV    892.8mV    16.4mV
648ps     39.83mV    528.7mV    5.966mV
842ps     7.006mV    114.6mV    1.441mV
1.046ns   2.257mV    14.33mV    552.8uV
10ns      184.6nV    729.6nV    232.6nV
